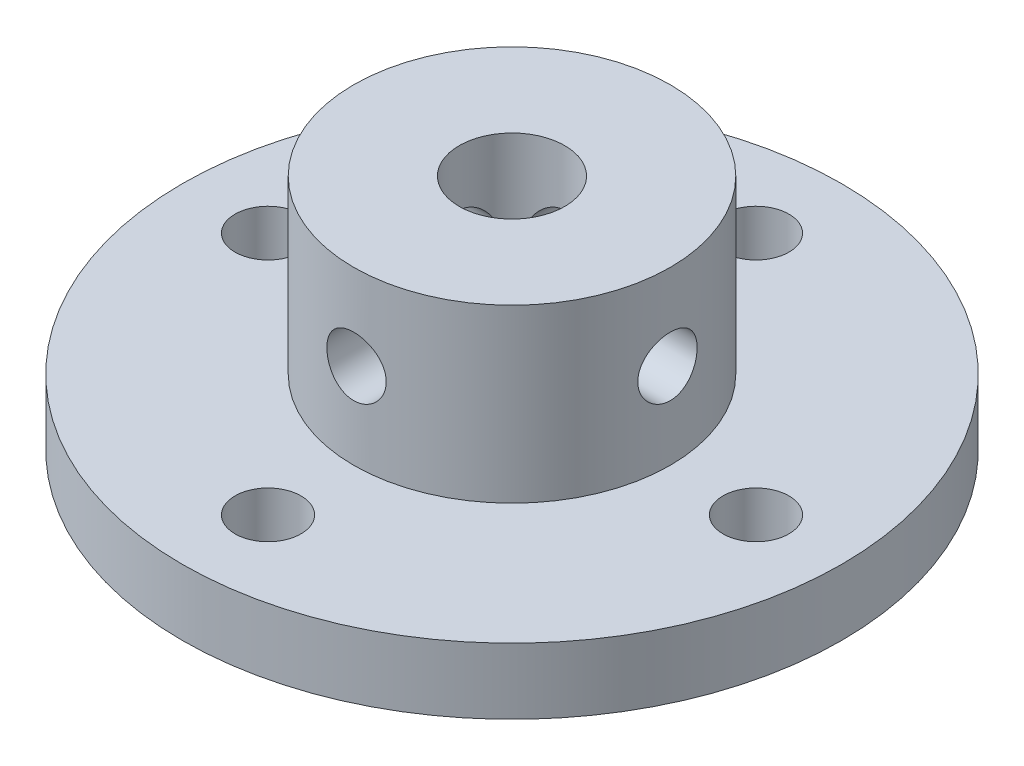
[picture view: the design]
ISO-10303-21;
HEADER;
FILE_DESCRIPTION(('STEP AP214'),'2;1');
FILE_NAME('part.step','',(''),(''),'','','');
FILE_SCHEMA(('AUTOMOTIVE_DESIGN { 1 0 10303 214 1 1 1 1 }'));
ENDSEC;
DATA;
#1=APPLICATION_CONTEXT('core data for automotive mechanical design processes');
#2=APPLICATION_PROTOCOL_DEFINITION('international standard','automotive_design',2000,#1);
#3=PRODUCT_CONTEXT('',#1,'mechanical');
#4=PRODUCT('Part','Part','',(#3));
#5=PRODUCT_RELATED_PRODUCT_CATEGORY('part','',(#4));
#6=PRODUCT_DEFINITION_FORMATION('','',#4);
#7=PRODUCT_DEFINITION_CONTEXT('part definition',#1,'design');
#8=PRODUCT_DEFINITION('design','',#6,#7);
#9=PRODUCT_DEFINITION_SHAPE('','',#8);
#10=(LENGTH_UNIT() NAMED_UNIT(*) SI_UNIT(.MILLI.,.METRE.));
#11=(NAMED_UNIT(*) PLANE_ANGLE_UNIT() SI_UNIT($,.RADIAN.));
#12=(NAMED_UNIT(*) SI_UNIT($,.STERADIAN.) SOLID_ANGLE_UNIT());
#13=UNCERTAINTY_MEASURE_WITH_UNIT(LENGTH_MEASURE(1.E-05),#10,'distance_accuracy_value','');
#14=(GEOMETRIC_REPRESENTATION_CONTEXT(3) GLOBAL_UNCERTAINTY_ASSIGNED_CONTEXT((#13)) GLOBAL_UNIT_ASSIGNED_CONTEXT((#10,
#11,#12)) REPRESENTATION_CONTEXT('',''));
#15=CARTESIAN_POINT('',(0.,0.,0.));
#16=DIRECTION('',(0.,0.,1.));
#17=DIRECTION('',(1.,0.,0.));
#18=AXIS2_PLACEMENT_3D('',#15,#16,#17);
#19=CARTESIAN_POINT('',(0.,5.,0.));
#20=DIRECTION('',(0.,-1.,0.));
#21=DIRECTION('',(0.,0.,-1.));
#22=AXIS2_PLACEMENT_3D('',#19,#20,#21);
#23=CYLINDRICAL_SURFACE('',#22,25.);
#24=CARTESIAN_POINT('',(0.,5.,0.));
#25=DIRECTION('',(0.,1.,0.));
#26=DIRECTION('',(0.,0.,1.));
#27=AXIS2_PLACEMENT_3D('',#24,#25,#26);
#28=CIRCLE('',#27,25.);
#29=CARTESIAN_POINT('',(0.,5.,25.));
#30=VERTEX_POINT('',#29);
#31=EDGE_CURVE('E52',#30,#30,#28,.T.);
#32=ORIENTED_EDGE('',*,*,#31,.F.);
#33=EDGE_LOOP('',(#32));
#34=FACE_BOUND('',#33,.T.);
#35=CARTESIAN_POINT('',(0.,0.,0.));
#36=DIRECTION('',(0.,1.,0.));
#37=DIRECTION('',(0.,0.,1.));
#38=AXIS2_PLACEMENT_3D('',#35,#36,#37);
#39=CIRCLE('',#38,25.);
#40=CARTESIAN_POINT('',(0.,0.,25.));
#41=VERTEX_POINT('',#40);
#42=EDGE_CURVE('E59',#41,#41,#39,.T.);
#43=ORIENTED_EDGE('',*,*,#42,.T.);
#44=EDGE_LOOP('',(#43));
#45=FACE_BOUND('',#44,.T.);
#46=ADVANCED_FACE('F41',(#34,#45),#23,.T.);
#47=CARTESIAN_POINT('',(0.,5.,0.));
#48=DIRECTION('',(0.,1.,0.));
#49=DIRECTION('',(0.,0.,1.));
#50=AXIS2_PLACEMENT_3D('',#47,#48,#49);
#51=PLANE('',#50);
#52=CARTESIAN_POINT('',(0.,5.,-18.5));
#53=DIRECTION('',(0.,1.,0.));
#54=DIRECTION('',(0.,0.,1.));
#55=AXIS2_PLACEMENT_3D('',#52,#53,#54);
#56=CIRCLE('',#55,2.5);
#57=CARTESIAN_POINT('',(0.,5.,-16.));
#58=VERTEX_POINT('',#57);
#59=EDGE_CURVE('E183',#58,#58,#56,.T.);
#60=ORIENTED_EDGE('',*,*,#59,.F.);
#61=EDGE_LOOP('',(#60));
#62=FACE_BOUND('',#61,.T.);
#63=CARTESIAN_POINT('',(18.5,5.,0.));
#64=DIRECTION('',(0.,1.,0.));
#65=DIRECTION('',(0.,0.,1.));
#66=AXIS2_PLACEMENT_3D('',#63,#64,#65);
#67=CIRCLE('',#66,2.5);
#68=CARTESIAN_POINT('',(18.5,5.,2.5));
#69=VERTEX_POINT('',#68);
#70=EDGE_CURVE('E178',#69,#69,#67,.T.);
#71=ORIENTED_EDGE('',*,*,#70,.F.);
#72=EDGE_LOOP('',(#71));
#73=FACE_BOUND('',#72,.T.);
#74=CARTESIAN_POINT('',(0.,5.,18.5));
#75=DIRECTION('',(0.,1.,0.));
#76=DIRECTION('',(0.,0.,1.));
#77=AXIS2_PLACEMENT_3D('',#74,#75,#76);
#78=CIRCLE('',#77,2.5);
#79=CARTESIAN_POINT('',(0.,5.,21.));
#80=VERTEX_POINT('',#79);
#81=EDGE_CURVE('E175',#80,#80,#78,.T.);
#82=ORIENTED_EDGE('',*,*,#81,.F.);
#83=EDGE_LOOP('',(#82));
#84=FACE_BOUND('',#83,.T.);
#85=CARTESIAN_POINT('',(-18.5,5.,0.));
#86=DIRECTION('',(0.,1.,0.));
#87=DIRECTION('',(0.,0.,1.));
#88=AXIS2_PLACEMENT_3D('',#85,#86,#87);
#89=CIRCLE('',#88,2.5);
#90=CARTESIAN_POINT('',(-18.5,5.,2.5));
#91=VERTEX_POINT('',#90);
#92=EDGE_CURVE('E168',#91,#91,#89,.T.);
#93=ORIENTED_EDGE('',*,*,#92,.F.);
#94=EDGE_LOOP('',(#93));
#95=FACE_BOUND('',#94,.T.);
#96=CARTESIAN_POINT('',(0.,5.,0.));
#97=DIRECTION('',(0.,1.,0.));
#98=DIRECTION('',(0.,0.,1.));
#99=AXIS2_PLACEMENT_3D('',#96,#97,#98);
#100=CIRCLE('',#99,12.);
#101=CARTESIAN_POINT('',(0.,5.,12.));
#102=VERTEX_POINT('',#101);
#103=EDGE_CURVE('E10',#102,#102,#100,.T.);
#104=ORIENTED_EDGE('',*,*,#103,.F.);
#105=EDGE_LOOP('',(#104));
#106=FACE_BOUND('',#105,.T.);
#107=ORIENTED_EDGE('',*,*,#31,.T.);
#108=EDGE_LOOP('',(#107));
#109=FACE_BOUND('',#108,.T.);
#110=ADVANCED_FACE('F119',(#62,#73,#84,#95,#106,#109),#51,.T.);
#111=CARTESIAN_POINT('',(0.,0.,0.));
#112=DIRECTION('',(0.,1.,0.));
#113=DIRECTION('',(0.,0.,1.));
#114=AXIS2_PLACEMENT_3D('',#111,#112,#113);
#115=PLANE('',#114);
#116=CARTESIAN_POINT('',(0.,0.,-18.5));
#117=DIRECTION('',(0.,1.,0.));
#118=DIRECTION('',(0.,0.,1.));
#119=AXIS2_PLACEMENT_3D('',#116,#117,#118);
#120=CIRCLE('',#119,2.5);
#121=CARTESIAN_POINT('',(0.,0.,-16.));
#122=VERTEX_POINT('',#121);
#123=EDGE_CURVE('E165',#122,#122,#120,.T.);
#124=ORIENTED_EDGE('',*,*,#123,.T.);
#125=EDGE_LOOP('',(#124));
#126=FACE_BOUND('',#125,.T.);
#127=CARTESIAN_POINT('',(18.5,0.,0.));
#128=DIRECTION('',(0.,1.,0.));
#129=DIRECTION('',(0.,0.,1.));
#130=AXIS2_PLACEMENT_3D('',#127,#128,#129);
#131=CIRCLE('',#130,2.5);
#132=CARTESIAN_POINT('',(18.5,0.,2.5));
#133=VERTEX_POINT('',#132);
#134=EDGE_CURVE('E181',#133,#133,#131,.T.);
#135=ORIENTED_EDGE('',*,*,#134,.T.);
#136=EDGE_LOOP('',(#135));
#137=FACE_BOUND('',#136,.T.);
#138=CARTESIAN_POINT('',(0.,0.,18.5));
#139=DIRECTION('',(0.,1.,0.));
#140=DIRECTION('',(0.,0.,1.));
#141=AXIS2_PLACEMENT_3D('',#138,#139,#140);
#142=CIRCLE('',#141,2.5);
#143=CARTESIAN_POINT('',(0.,0.,21.));
#144=VERTEX_POINT('',#143);
#145=EDGE_CURVE('E174',#144,#144,#142,.T.);
#146=ORIENTED_EDGE('',*,*,#145,.T.);
#147=EDGE_LOOP('',(#146));
#148=FACE_BOUND('',#147,.T.);
#149=CARTESIAN_POINT('',(-18.5,0.,0.));
#150=DIRECTION('',(0.,1.,0.));
#151=DIRECTION('',(0.,0.,1.));
#152=AXIS2_PLACEMENT_3D('',#149,#150,#151);
#153=CIRCLE('',#152,2.5);
#154=CARTESIAN_POINT('',(-18.5,0.,2.5));
#155=VERTEX_POINT('',#154);
#156=EDGE_CURVE('E169',#155,#155,#153,.T.);
#157=ORIENTED_EDGE('',*,*,#156,.T.);
#158=EDGE_LOOP('',(#157));
#159=FACE_BOUND('',#158,.T.);
#160=CARTESIAN_POINT('',(0.,0.,0.));
#161=DIRECTION('',(0.,1.,0.));
#162=DIRECTION('',(0.,0.,1.));
#163=AXIS2_PLACEMENT_3D('',#160,#161,#162);
#164=CIRCLE('',#163,4.);
#165=CARTESIAN_POINT('',(0.,0.,4.));
#166=VERTEX_POINT('',#165);
#167=EDGE_CURVE('E160',#166,#166,#164,.T.);
#168=ORIENTED_EDGE('',*,*,#167,.T.);
#169=EDGE_LOOP('',(#168));
#170=FACE_BOUND('',#169,.T.);
#171=ORIENTED_EDGE('',*,*,#42,.F.);
#172=EDGE_LOOP('',(#171));
#173=FACE_BOUND('',#172,.T.);
#174=ADVANCED_FACE('F117',(#126,#137,#148,#159,#170,#173),#115,.F.);
#175=CARTESIAN_POINT('',(0.,18.,0.));
#176=DIRECTION('',(0.,-1.,0.));
#177=DIRECTION('',(0.,0.,-1.));
#178=AXIS2_PLACEMENT_3D('',#175,#176,#177);
#179=CYLINDRICAL_SURFACE('',#178,12.);
#180=CARTESIAN_POINT('',(0.,13.75,-12.));
#181=CARTESIAN_POINT('',(-0.125207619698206,13.7499952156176,-11.9999977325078));
#182=CARTESIAN_POINT('',(-0.250477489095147,13.7395133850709,-11.9980201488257));
#183=CARTESIAN_POINT('',(-0.497487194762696,13.6978900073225,-11.9903217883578));
#184=CARTESIAN_POINT('',(-0.619223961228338,13.6667310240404,-11.9845978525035));
#185=CARTESIAN_POINT('',(-0.855559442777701,13.584740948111,-11.9700470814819));
#186=CARTESIAN_POINT('',(-0.970164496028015,13.5339276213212,-11.9612230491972));
#187=CARTESIAN_POINT('',(-1.18921195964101,13.4141216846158,-11.9414356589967));
#188=CARTESIAN_POINT('',(-1.29365519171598,13.3451305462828,-11.9304724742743));
#189=CARTESIAN_POINT('',(-1.49067557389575,13.1900503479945,-11.9074700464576));
#190=CARTESIAN_POINT('',(-1.58311343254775,13.1037858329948,-11.8954205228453));
#191=CARTESIAN_POINT('',(-1.75229409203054,12.9169850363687,-11.8716797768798));
#192=CARTESIAN_POINT('',(-1.82903576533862,12.8164477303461,-11.8599885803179));
#193=CARTESIAN_POINT('',(-1.96522497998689,12.602970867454,-11.8381882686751));
#194=CARTESIAN_POINT('',(-2.02453082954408,12.4899394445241,-11.8280924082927));
#195=CARTESIAN_POINT('',(-2.12325786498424,12.2552966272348,-11.8107706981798));
#196=CARTESIAN_POINT('',(-2.16268076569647,12.1336859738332,-11.8035446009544));
#197=CARTESIAN_POINT('',(-2.2200758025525,11.8868271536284,-11.7928840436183));
#198=CARTESIAN_POINT('',(-2.23829085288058,11.7616373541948,-11.7894066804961));
#199=CARTESIAN_POINT('',(-2.2535071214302,11.5099339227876,-11.7865079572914));
#200=CARTESIAN_POINT('',(-2.25051024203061,11.3834204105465,-11.7870862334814));
#201=CARTESIAN_POINT('',(-2.22358469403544,11.1344207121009,-11.7921943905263));
#202=CARTESIAN_POINT('',(-2.19993224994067,11.0119034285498,-11.79667212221));
#203=CARTESIAN_POINT('',(-2.1328019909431,10.7726073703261,-11.80899274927));
#204=CARTESIAN_POINT('',(-2.08932333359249,10.655828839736,-11.8168357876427));
#205=CARTESIAN_POINT('',(-1.9835047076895,10.4305169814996,-11.8350578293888));
#206=CARTESIAN_POINT('',(-1.92105320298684,10.3220372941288,-11.8454517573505));
#207=CARTESIAN_POINT('',(-1.77914053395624,10.1169929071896,-11.8675945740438));
#208=CARTESIAN_POINT('',(-1.69967764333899,10.0204294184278,-11.8793436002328));
#209=CARTESIAN_POINT('',(-1.52450858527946,9.84036256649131,-11.9031000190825));
#210=CARTESIAN_POINT('',(-1.42856615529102,9.75708902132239,-11.9151085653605));
#211=CARTESIAN_POINT('',(-1.22395205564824,9.60778413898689,-11.9378607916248));
#212=CARTESIAN_POINT('',(-1.11528025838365,9.54175297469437,-11.9486044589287));
#213=CARTESIAN_POINT('',(-0.888052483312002,9.42877336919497,-11.9676380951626));
#214=CARTESIAN_POINT('',(-0.76948434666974,9.38184883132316,-11.9759249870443));
#215=CARTESIAN_POINT('',(-0.525958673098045,9.30864686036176,-11.9890875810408));
#216=CARTESIAN_POINT('',(-0.401001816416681,9.28236723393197,-11.9939636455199));
#217=CARTESIAN_POINT('',(-0.150222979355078,9.25152095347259,-11.9997054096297));
#218=CARTESIAN_POINT('',(-0.0244410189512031,9.24663941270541,-12.0006292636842));
#219=CARTESIAN_POINT('',(0.226141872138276,9.25788321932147,-11.9985231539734));
#220=CARTESIAN_POINT('',(0.350942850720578,9.27400753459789,-11.9954933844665));
#221=CARTESIAN_POINT('',(0.595022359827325,9.32654355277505,-11.9858566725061));
#222=CARTESIAN_POINT('',(0.714336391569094,9.36279592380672,-11.9792778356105));
#223=CARTESIAN_POINT('',(0.945192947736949,9.45438656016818,-11.9632776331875));
#224=CARTESIAN_POINT('',(1.05673494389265,9.50972612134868,-11.95385607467));
#225=CARTESIAN_POINT('',(1.27022500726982,9.63861719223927,-11.933070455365));
#226=CARTESIAN_POINT('',(1.37205491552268,9.71236110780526,-11.9216862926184));
#227=CARTESIAN_POINT('',(1.56200748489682,9.87570720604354,-11.8982901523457));
#228=CARTESIAN_POINT('',(1.6501288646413,9.96531086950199,-11.8862781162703));
#229=CARTESIAN_POINT('',(1.81135943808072,10.1592584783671,-11.8627871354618));
#230=CARTESIAN_POINT('',(1.88425374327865,10.2637823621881,-11.8513173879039));
#231=CARTESIAN_POINT('',(2.0114501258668,10.4837764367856,-11.830394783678));
#232=CARTESIAN_POINT('',(2.06575289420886,10.5992462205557,-11.8209418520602));
#233=CARTESIAN_POINT('',(2.15392010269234,10.8373088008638,-11.8051953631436));
#234=CARTESIAN_POINT('',(2.18788303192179,10.959864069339,-11.7988866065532));
#235=CARTESIAN_POINT('',(2.23471018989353,11.2090708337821,-11.7901080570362));
#236=CARTESIAN_POINT('',(2.24757679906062,11.3357218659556,-11.7876378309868));
#237=CARTESIAN_POINT('',(2.25176643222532,11.5873724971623,-11.7868379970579));
#238=CARTESIAN_POINT('',(2.24342842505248,11.7123663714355,-11.7884432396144));
#239=CARTESIAN_POINT('',(2.20618763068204,11.9591371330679,-11.7954690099));
#240=CARTESIAN_POINT('',(2.17728496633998,12.0809140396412,-11.8008895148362));
#241=CARTESIAN_POINT('',(2.09987831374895,12.3176117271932,-11.8149076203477));
#242=CARTESIAN_POINT('',(2.05141103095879,12.4325448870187,-11.8234992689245));
#243=CARTESIAN_POINT('',(1.93628803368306,12.6527023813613,-11.8428958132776));
#244=CARTESIAN_POINT('',(1.86963103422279,12.7579260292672,-11.8537008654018));
#245=CARTESIAN_POINT('',(1.71884231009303,12.9573755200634,-11.8765089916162));
#246=CARTESIAN_POINT('',(1.63446389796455,13.0514131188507,-11.8885275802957));
#247=CARTESIAN_POINT('',(1.45114189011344,13.2241077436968,-11.912292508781));
#248=CARTESIAN_POINT('',(1.35219495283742,13.3027612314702,-11.9240387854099));
#249=CARTESIAN_POINT('',(1.14147741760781,13.4431164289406,-11.9460596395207));
#250=CARTESIAN_POINT('',(1.02959938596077,13.504659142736,-11.9563200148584));
#251=CARTESIAN_POINT('',(0.796935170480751,13.6079764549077,-11.9740742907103));
#252=CARTESIAN_POINT('',(0.676157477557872,13.6497696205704,-11.9815707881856));
#253=CARTESIAN_POINT('',(0.462520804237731,13.703915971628,-11.9914243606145));
#254=CARTESIAN_POINT('',(0.370910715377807,13.7211679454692,-11.9946220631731));
#255=CARTESIAN_POINT('',(0.186211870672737,13.7442115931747,-11.9989106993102));
#256=CARTESIAN_POINT('',(0.0931231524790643,13.7500035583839,-12.0000016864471));
#257=CARTESIAN_POINT('',(0.,13.75,-12.));
#258=B_SPLINE_CURVE_WITH_KNOTS('',3,(#180,#181,#182,#183,#184,#185,#186,#187,#188,#189,#190,
#191,#192,#193,#194,#195,#196,#197,#198,#199,#200,#201,#202,#203,#204,#205,#206,#207,#208,#209,
#210,#211,#212,#213,#214,#215,#216,#217,#218,#219,#220,#221,#222,#223,#224,#225,#226,#227,#228,
#229,#230,#231,#232,#233,#234,#235,#236,#237,#238,#239,#240,#241,#242,#243,#244,#245,#246,#247,
#248,#249,#250,#251,#252,#253,#254,#255,#256,#257),.UNSPECIFIED.,.T.,.F.,(4,2,2,2,2,2,2,2,2,2,2,
2,2,2,2,2,2,2,2,2,2,2,2,2,2,2,2,2,2,2,2,2,2,2,2,2,2,2,4),(0.,0.375282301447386,
0.750881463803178,1.12614190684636,1.50137198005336,1.88062677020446,2.25990879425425,
2.64219285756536,3.02444394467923,3.40227227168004,3.78006671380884,4.15288500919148,
4.5257191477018,4.90078893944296,5.27589681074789,5.65691652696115,6.03794006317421,
6.41943882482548,6.80089705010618,7.17672261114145,7.55252970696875,7.92540350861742,
8.29830263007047,8.67527667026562,9.05228592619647,9.43430155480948,9.81630298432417,
10.1964394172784,10.5765329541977,10.9505887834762,11.3246423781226,11.6979974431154,
12.0713788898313,12.4503505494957,12.8294092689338,13.2118807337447,13.5939919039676,
13.8731151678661,14.1522313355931),.UNSPECIFIED.);
#259=CARTESIAN_POINT('',(0.,13.75,-12.));
#260=VERTEX_POINT('',#259);
#261=EDGE_CURVE('E72',#260,#260,#258,.T.);
#262=ORIENTED_EDGE('',*,*,#261,.T.);
#263=EDGE_LOOP('',(#262));
#264=FACE_BOUND('',#263,.T.);
#265=CARTESIAN_POINT('',(2.25,11.5,11.7871752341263));
#266=CARTESIAN_POINT('',(2.24999519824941,11.3748141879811,11.787177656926));
#267=CARTESIAN_POINT('',(2.23951689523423,11.2495660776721,11.7891911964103));
#268=CARTESIAN_POINT('',(2.19790879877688,11.0026015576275,11.7970177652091));
#269=CARTESIAN_POINT('',(2.1667614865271,10.8808882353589,11.8028340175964));
#270=CARTESIAN_POINT('',(2.08480553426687,10.6446023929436,11.817584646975));
#271=CARTESIAN_POINT('',(2.03401520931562,10.530023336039,11.8265161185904));
#272=CARTESIAN_POINT('',(1.91426348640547,10.3110196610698,11.8464873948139));
#273=CARTESIAN_POINT('',(1.84530350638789,10.2065942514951,11.8575270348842));
#274=CARTESIAN_POINT('',(1.69025518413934,10.0095547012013,11.8806242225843));
#275=CARTESIAN_POINT('',(1.60398439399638,9.9170852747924,11.8926917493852));
#276=CARTESIAN_POINT('',(1.41715766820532,9.74784341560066,11.9163968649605));
#277=CARTESIAN_POINT('',(1.31660079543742,9.67107201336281,11.9280344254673));
#278=CARTESIAN_POINT('',(1.10310584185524,9.53485093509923,11.9496752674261));
#279=CARTESIAN_POINT('',(0.990079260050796,9.47553769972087,11.9596654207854));
#280=CARTESIAN_POINT('',(0.755446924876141,9.3767956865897,11.976774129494));
#281=CARTESIAN_POINT('',(0.633841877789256,9.33736527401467,11.983892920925));
#282=CARTESIAN_POINT('',(0.387004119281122,9.2799556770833,11.9943863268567));
#283=CARTESIAN_POINT('',(0.261829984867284,9.26173254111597,11.9978034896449));
#284=CARTESIAN_POINT('',(0.0101575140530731,9.2464946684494,12.0006552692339));
#285=CARTESIAN_POINT('',(-0.116340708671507,9.24947812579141,12.0000902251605));
#286=CARTESIAN_POINT('',(-0.365397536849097,9.27638165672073,11.9950745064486));
#287=CARTESIAN_POINT('',(-0.487985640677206,9.30003905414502,11.9906725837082));
#288=CARTESIAN_POINT('',(-0.727420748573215,9.36720347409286,11.9785323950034));
#289=CARTESIAN_POINT('',(-0.844267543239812,9.41071122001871,11.9707940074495));
#290=CARTESIAN_POINT('',(-1.06966509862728,9.51659159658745,11.9527689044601));
#291=CARTESIAN_POINT('',(-1.1781653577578,9.57906923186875,11.9424680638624));
#292=CARTESIAN_POINT('',(-1.38323996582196,9.72103850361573,11.9204572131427));
#293=CARTESIAN_POINT('',(-1.47981310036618,9.80053187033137,11.9087470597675));
#294=CARTESIAN_POINT('',(-1.65984842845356,9.9757235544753,11.8850027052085));
#295=CARTESIAN_POINT('',(-1.74308686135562,10.0716516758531,11.8729662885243));
#296=CARTESIAN_POINT('',(-1.89232757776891,10.2762242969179,11.8500976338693));
#297=CARTESIAN_POINT('',(-1.95832960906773,10.384868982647,11.8392654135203));
#298=CARTESIAN_POINT('',(-2.07128778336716,10.612087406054,11.8200283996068));
#299=CARTESIAN_POINT('',(-2.11821140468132,10.730677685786,11.8116277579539));
#300=CARTESIAN_POINT('',(-2.19140485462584,10.9742517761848,11.7982686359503));
#301=CARTESIAN_POINT('',(-2.21767702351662,11.0992348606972,11.7933097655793));
#302=CARTESIAN_POINT('',(-2.24849508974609,11.3500289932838,11.7874728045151));
#303=CARTESIAN_POINT('',(-2.25336246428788,11.4757991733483,11.786534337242));
#304=CARTESIAN_POINT('',(-2.24209453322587,11.7263551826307,11.7886828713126));
#305=CARTESIAN_POINT('',(-2.2259602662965,11.8511410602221,11.7917696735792));
#306=CARTESIAN_POINT('',(-2.17342302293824,12.0951293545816,11.8015647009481));
#307=CARTESIAN_POINT('',(-2.13718857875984,12.2143693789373,11.8082428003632));
#308=CARTESIAN_POINT('',(-2.0456583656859,12.4450857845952,11.8244420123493));
#309=CARTESIAN_POINT('',(-1.99036119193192,12.556561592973,11.8339633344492));
#310=CARTESIAN_POINT('',(-1.8615352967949,12.7700014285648,11.8549136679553));
#311=CARTESIAN_POINT('',(-1.78780349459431,12.8718408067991,11.8663634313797));
#312=CARTESIAN_POINT('',(-1.6244751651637,13.0618180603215,11.8898221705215));
#313=CARTESIAN_POINT('',(-1.53487721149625,13.1499547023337,11.9018311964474));
#314=CARTESIAN_POINT('',(-1.34092412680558,13.3112256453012,11.9252493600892));
#315=CARTESIAN_POINT('',(-1.23638780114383,13.384143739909,11.9366483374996));
#316=CARTESIAN_POINT('',(-1.01636178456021,13.5113818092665,11.9573910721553));
#317=CARTESIAN_POINT('',(-0.90087251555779,13.5657025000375,11.9667349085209));
#318=CARTESIAN_POINT('',(-0.662816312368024,13.6538801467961,11.9822708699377));
#319=CARTESIAN_POINT('',(-0.54028981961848,13.6878432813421,11.9884793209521));
#320=CARTESIAN_POINT('',(-0.291144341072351,13.7346805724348,11.9971146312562));
#321=CARTESIAN_POINT('',(-0.164525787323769,13.7475569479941,11.9995418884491));
#322=CARTESIAN_POINT('',(0.0871361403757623,13.7517779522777,12.0003334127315));
#323=CARTESIAN_POINT('',(0.212173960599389,13.7434491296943,11.998759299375));
#324=CARTESIAN_POINT('',(0.459035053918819,13.7062113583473,11.991852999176));
#325=CARTESIAN_POINT('',(0.580858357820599,13.6773026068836,11.9865208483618));
#326=CARTESIAN_POINT('',(0.817659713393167,13.5998631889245,11.9726975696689));
#327=CARTESIAN_POINT('',(0.932649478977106,13.5513672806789,11.9642120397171));
#328=CARTESIAN_POINT('',(1.15290844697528,13.4361693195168,11.9450005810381));
#329=CARTESIAN_POINT('',(1.25817699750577,13.3694660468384,11.9342745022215));
#330=CARTESIAN_POINT('',(1.45763254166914,13.2186228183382,11.9115716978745));
#331=CARTESIAN_POINT('',(1.5516393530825,13.1342469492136,11.8995792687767));
#332=CARTESIAN_POINT('',(1.72427304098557,12.9509431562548,11.8757945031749));
#333=CARTESIAN_POINT('',(1.802896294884,12.8520118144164,11.8640022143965));
#334=CARTESIAN_POINT('',(1.94321450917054,12.6413103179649,11.8418336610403));
#335=CARTESIAN_POINT('',(2.00474610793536,12.5294298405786,11.8314715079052));
#336=CARTESIAN_POINT('',(2.10804198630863,12.2967613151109,11.8135062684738));
#337=CARTESIAN_POINT('',(2.14982492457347,12.175981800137,11.8059005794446));
#338=CARTESIAN_POINT('',(2.20394589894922,11.9623715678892,11.7958952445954));
#339=CARTESIAN_POINT('',(2.22118658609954,11.8707914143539,11.7926446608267));
#340=CARTESIAN_POINT('',(2.24421526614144,11.6861522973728,11.7882837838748));
#341=CARTESIAN_POINT('',(2.25000357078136,11.5930933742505,11.7871734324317));
#342=CARTESIAN_POINT('',(2.25,11.5,11.7871752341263));
#343=B_SPLINE_CURVE_WITH_KNOTS('',3,(#265,#266,#267,#268,#269,#270,#271,#272,#273,#274,#275,
#276,#277,#278,#279,#280,#281,#282,#283,#284,#285,#286,#287,#288,#289,#290,#291,#292,#293,#294,
#295,#296,#297,#298,#299,#300,#301,#302,#303,#304,#305,#306,#307,#308,#309,#310,#311,#312,#313,
#314,#315,#316,#317,#318,#319,#320,#321,#322,#323,#324,#325,#326,#327,#328,#329,#330,#331,#332,
#333,#334,#335,#336,#337,#338,#339,#340,#341,#342),.UNSPECIFIED.,.T.,.F.,(4,2,2,2,2,2,2,2,2,2,2,
2,2,2,2,2,2,2,2,2,2,2,2,2,2,2,2,2,2,2,2,2,2,2,2,2,2,2,4),(0.,0.375216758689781,0.75075195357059,
1.12593784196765,1.50109445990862,1.88043503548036,2.25980050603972,2.64205656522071,
3.0242811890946,3.40206413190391,3.77981490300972,4.15283475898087,4.52586820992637,
4.90100537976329,5.27618071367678,5.65710922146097,6.038043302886,6.419624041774,
6.80116153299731,7.17694872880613,7.55271734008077,7.92538188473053,8.29807389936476,
8.67506793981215,9.05209589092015,9.43416188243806,9.81621316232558,10.1962540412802,
10.57625492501,10.9504395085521,11.3246205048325,11.6981403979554,12.0716853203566,
12.4505769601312,12.8295577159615,13.2120450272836,13.5941702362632,13.8732046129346,
14.1522313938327),.UNSPECIFIED.);
#344=CARTESIAN_POINT('',(2.25,11.5,11.7871752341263));
#345=VERTEX_POINT('',#344);
#346=EDGE_CURVE('E121',#345,#345,#343,.T.);
#347=ORIENTED_EDGE('',*,*,#346,.T.);
#348=EDGE_LOOP('',(#347));
#349=FACE_BOUND('',#348,.T.);
#350=CARTESIAN_POINT('',(-11.7871752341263,11.5,-2.25));
#351=CARTESIAN_POINT('',(-11.787177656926,11.6251858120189,-2.24999519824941));
#352=CARTESIAN_POINT('',(-11.7891911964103,11.7504339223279,-2.23951689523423));
#353=CARTESIAN_POINT('',(-11.7970177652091,11.9973984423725,-2.19790879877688));
#354=CARTESIAN_POINT('',(-11.8028340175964,12.1191117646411,-2.1667614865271));
#355=CARTESIAN_POINT('',(-11.817584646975,12.3553976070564,-2.08480553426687));
#356=CARTESIAN_POINT('',(-11.8265161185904,12.469976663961,-2.03401520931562));
#357=CARTESIAN_POINT('',(-11.8464873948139,12.6889803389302,-1.91426348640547));
#358=CARTESIAN_POINT('',(-11.8575270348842,12.7934057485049,-1.84530350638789));
#359=CARTESIAN_POINT('',(-11.8806242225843,12.9904452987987,-1.69025518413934));
#360=CARTESIAN_POINT('',(-11.8926917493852,13.0829147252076,-1.60398439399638));
#361=CARTESIAN_POINT('',(-11.9163968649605,13.2521565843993,-1.41715766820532));
#362=CARTESIAN_POINT('',(-11.9280344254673,13.3289279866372,-1.31660079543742));
#363=CARTESIAN_POINT('',(-11.9496752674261,13.4651490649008,-1.10310584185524));
#364=CARTESIAN_POINT('',(-11.9596654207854,13.5244623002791,-0.990079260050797));
#365=CARTESIAN_POINT('',(-11.976774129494,13.6232043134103,-0.755446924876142));
#366=CARTESIAN_POINT('',(-11.983892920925,13.6626347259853,-0.633841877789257));
#367=CARTESIAN_POINT('',(-11.9943863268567,13.7200443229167,-0.387004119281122));
#368=CARTESIAN_POINT('',(-11.9978034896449,13.738267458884,-0.261829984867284));
#369=CARTESIAN_POINT('',(-12.0006552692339,13.7535053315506,-0.0101575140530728));
#370=CARTESIAN_POINT('',(-12.0000902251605,13.7505218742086,0.116340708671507));
#371=CARTESIAN_POINT('',(-11.9950745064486,13.7236183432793,0.365397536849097));
#372=CARTESIAN_POINT('',(-11.9906725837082,13.699960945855,0.487985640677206));
#373=CARTESIAN_POINT('',(-11.9785323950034,13.6327965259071,0.727420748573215));
#374=CARTESIAN_POINT('',(-11.9707940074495,13.5892887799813,0.844267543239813));
#375=CARTESIAN_POINT('',(-11.9527689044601,13.4834084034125,1.06966509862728));
#376=CARTESIAN_POINT('',(-11.9424680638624,13.4209307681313,1.1781653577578));
#377=CARTESIAN_POINT('',(-11.9204572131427,13.2789614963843,1.38323996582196));
#378=CARTESIAN_POINT('',(-11.9087470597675,13.1994681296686,1.47981310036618));
#379=CARTESIAN_POINT('',(-11.8850027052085,13.0242764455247,1.65984842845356));
#380=CARTESIAN_POINT('',(-11.8729662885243,12.9283483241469,1.74308686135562));
#381=CARTESIAN_POINT('',(-11.8500976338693,12.7237757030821,1.89232757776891));
#382=CARTESIAN_POINT('',(-11.8392654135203,12.615131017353,1.95832960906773));
#383=CARTESIAN_POINT('',(-11.8200283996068,12.387912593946,2.07128778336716));
#384=CARTESIAN_POINT('',(-11.8116277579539,12.269322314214,2.11821140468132));
#385=CARTESIAN_POINT('',(-11.7982686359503,12.0257482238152,2.19140485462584));
#386=CARTESIAN_POINT('',(-11.7933097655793,11.9007651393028,2.21767702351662));
#387=CARTESIAN_POINT('',(-11.7874728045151,11.6499710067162,2.24849508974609));
#388=CARTESIAN_POINT('',(-11.786534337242,11.5242008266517,2.25336246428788));
#389=CARTESIAN_POINT('',(-11.7886828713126,11.2736448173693,2.24209453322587));
#390=CARTESIAN_POINT('',(-11.7917696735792,11.1488589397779,2.2259602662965));
#391=CARTESIAN_POINT('',(-11.8015647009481,10.9048706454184,2.17342302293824));
#392=CARTESIAN_POINT('',(-11.8082428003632,10.7856306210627,2.13718857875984));
#393=CARTESIAN_POINT('',(-11.8244420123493,10.5549142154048,2.0456583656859));
#394=CARTESIAN_POINT('',(-11.8339633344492,10.443438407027,1.99036119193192));
#395=CARTESIAN_POINT('',(-11.8549136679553,10.2299985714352,1.8615352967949));
#396=CARTESIAN_POINT('',(-11.8663634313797,10.1281591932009,1.78780349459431));
#397=CARTESIAN_POINT('',(-11.8898221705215,9.9381819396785,1.6244751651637));
#398=CARTESIAN_POINT('',(-11.9018311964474,9.85004529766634,1.53487721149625));
#399=CARTESIAN_POINT('',(-11.9252493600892,9.68877435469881,1.34092412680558));
#400=CARTESIAN_POINT('',(-11.9366483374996,9.61585626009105,1.23638780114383));
#401=CARTESIAN_POINT('',(-11.9573910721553,9.4886181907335,1.01636178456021));
#402=CARTESIAN_POINT('',(-11.9667349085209,9.43429749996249,0.900872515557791));
#403=CARTESIAN_POINT('',(-11.9822708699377,9.34611985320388,0.662816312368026));
#404=CARTESIAN_POINT('',(-11.9884793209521,9.31215671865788,0.540289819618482));
#405=CARTESIAN_POINT('',(-11.9971146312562,9.26531942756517,0.291144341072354));
#406=CARTESIAN_POINT('',(-11.9995418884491,9.25244305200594,0.16452578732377));
#407=CARTESIAN_POINT('',(-12.0003334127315,9.24822204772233,-0.0871361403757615));
#408=CARTESIAN_POINT('',(-11.998759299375,9.25655087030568,-0.212173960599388));
#409=CARTESIAN_POINT('',(-11.991852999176,9.29378864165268,-0.459035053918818));
#410=CARTESIAN_POINT('',(-11.9865208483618,9.32269739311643,-0.580858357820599));
#411=CARTESIAN_POINT('',(-11.9726975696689,9.40013681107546,-0.817659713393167));
#412=CARTESIAN_POINT('',(-11.9642120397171,9.44863271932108,-0.932649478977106));
#413=CARTESIAN_POINT('',(-11.9450005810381,9.56383068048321,-1.15290844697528));
#414=CARTESIAN_POINT('',(-11.9342745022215,9.6305339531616,-1.25817699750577));
#415=CARTESIAN_POINT('',(-11.9115716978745,9.78137718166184,-1.45763254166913));
#416=CARTESIAN_POINT('',(-11.8995792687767,9.86575305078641,-1.5516393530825));
#417=CARTESIAN_POINT('',(-11.8757945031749,10.0490568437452,-1.72427304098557));
#418=CARTESIAN_POINT('',(-11.8640022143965,10.1479881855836,-1.802896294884));
#419=CARTESIAN_POINT('',(-11.8418336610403,10.3586896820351,-1.94321450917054));
#420=CARTESIAN_POINT('',(-11.8314715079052,10.4705701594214,-2.00474610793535));
#421=CARTESIAN_POINT('',(-11.8135062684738,10.7032386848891,-2.10804198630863));
#422=CARTESIAN_POINT('',(-11.8059005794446,10.824018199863,-2.14982492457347));
#423=CARTESIAN_POINT('',(-11.7958952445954,11.0376284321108,-2.20394589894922));
#424=CARTESIAN_POINT('',(-11.7926446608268,11.1292085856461,-2.22118658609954));
#425=CARTESIAN_POINT('',(-11.7882837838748,11.3138477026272,-2.24421526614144));
#426=CARTESIAN_POINT('',(-11.7871734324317,11.4069066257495,-2.25000357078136));
#427=CARTESIAN_POINT('',(-11.7871752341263,11.5,-2.25));
#428=B_SPLINE_CURVE_WITH_KNOTS('',3,(#350,#351,#352,#353,#354,#355,#356,#357,#358,#359,#360,
#361,#362,#363,#364,#365,#366,#367,#368,#369,#370,#371,#372,#373,#374,#375,#376,#377,#378,#379,
#380,#381,#382,#383,#384,#385,#386,#387,#388,#389,#390,#391,#392,#393,#394,#395,#396,#397,#398,
#399,#400,#401,#402,#403,#404,#405,#406,#407,#408,#409,#410,#411,#412,#413,#414,#415,#416,#417,
#418,#419,#420,#421,#422,#423,#424,#425,#426,#427),.UNSPECIFIED.,.T.,.F.,(4,2,2,2,2,2,2,2,2,2,2,
2,2,2,2,2,2,2,2,2,2,2,2,2,2,2,2,2,2,2,2,2,2,2,2,2,2,2,4),(0.,0.375216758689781,0.75075195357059,
1.12593784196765,1.50109445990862,1.88043503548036,2.25980050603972,2.64205656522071,
3.0242811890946,3.40206413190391,3.77981490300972,4.15283475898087,4.52586820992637,
4.90100537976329,5.27618071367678,5.65710922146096,6.038043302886,6.419624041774,
6.80116153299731,7.17694872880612,7.55271734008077,7.92538188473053,8.29807389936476,
8.67506793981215,9.05209589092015,9.43416188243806,9.81621316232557,10.1962540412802,
10.57625492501,10.9504395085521,11.3246205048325,11.6981403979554,12.0716853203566,
12.4505769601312,12.8295577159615,13.2120450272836,13.5941702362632,13.8732046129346,
14.1522313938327),.UNSPECIFIED.);
#429=CARTESIAN_POINT('',(-11.7871752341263,11.5,-2.25));
#430=VERTEX_POINT('',#429);
#431=EDGE_CURVE('E104',#430,#430,#428,.T.);
#432=ORIENTED_EDGE('',*,*,#431,.T.);
#433=EDGE_LOOP('',(#432));
#434=FACE_BOUND('',#433,.T.);
#435=CARTESIAN_POINT('',(11.7871752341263,11.5,-2.25));
#436=CARTESIAN_POINT('',(11.787177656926,11.3748141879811,-2.24999519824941));
#437=CARTESIAN_POINT('',(11.7891911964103,11.2495660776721,-2.23951689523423));
#438=CARTESIAN_POINT('',(11.7970177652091,11.0026015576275,-2.19790879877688));
#439=CARTESIAN_POINT('',(11.8028340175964,10.8808882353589,-2.1667614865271));
#440=CARTESIAN_POINT('',(11.817584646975,10.6446023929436,-2.08480553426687));
#441=CARTESIAN_POINT('',(11.8265161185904,10.530023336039,-2.03401520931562));
#442=CARTESIAN_POINT('',(11.8464873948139,10.3110196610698,-1.91426348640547));
#443=CARTESIAN_POINT('',(11.8575270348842,10.2065942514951,-1.84530350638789));
#444=CARTESIAN_POINT('',(11.8806242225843,10.0095547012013,-1.69025518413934));
#445=CARTESIAN_POINT('',(11.8926917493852,9.9170852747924,-1.60398439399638));
#446=CARTESIAN_POINT('',(11.9163968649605,9.74784341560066,-1.41715766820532));
#447=CARTESIAN_POINT('',(11.9280344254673,9.67107201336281,-1.31660079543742));
#448=CARTESIAN_POINT('',(11.9496752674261,9.53485093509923,-1.10310584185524));
#449=CARTESIAN_POINT('',(11.9596654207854,9.47553769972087,-0.990079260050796));
#450=CARTESIAN_POINT('',(11.976774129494,9.3767956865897,-0.755446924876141));
#451=CARTESIAN_POINT('',(11.983892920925,9.33736527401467,-0.633841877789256));
#452=CARTESIAN_POINT('',(11.9943863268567,9.2799556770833,-0.387004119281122));
#453=CARTESIAN_POINT('',(11.9978034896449,9.26173254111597,-0.261829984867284));
#454=CARTESIAN_POINT('',(12.0006552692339,9.2464946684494,-0.0101575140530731));
#455=CARTESIAN_POINT('',(12.0000902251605,9.24947812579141,0.116340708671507));
#456=CARTESIAN_POINT('',(11.9950745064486,9.27638165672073,0.365397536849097));
#457=CARTESIAN_POINT('',(11.9906725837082,9.30003905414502,0.487985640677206));
#458=CARTESIAN_POINT('',(11.9785323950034,9.36720347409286,0.727420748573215));
#459=CARTESIAN_POINT('',(11.9707940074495,9.41071122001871,0.844267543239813));
#460=CARTESIAN_POINT('',(11.9527689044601,9.51659159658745,1.06966509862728));
#461=CARTESIAN_POINT('',(11.9424680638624,9.57906923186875,1.1781653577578));
#462=CARTESIAN_POINT('',(11.9204572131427,9.72103850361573,1.38323996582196));
#463=CARTESIAN_POINT('',(11.9087470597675,9.80053187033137,1.47981310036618));
#464=CARTESIAN_POINT('',(11.8850027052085,9.9757235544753,1.65984842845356));
#465=CARTESIAN_POINT('',(11.8729662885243,10.0716516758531,1.74308686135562));
#466=CARTESIAN_POINT('',(11.8500976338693,10.2762242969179,1.89232757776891));
#467=CARTESIAN_POINT('',(11.8392654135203,10.384868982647,1.95832960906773));
#468=CARTESIAN_POINT('',(11.8200283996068,10.612087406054,2.07128778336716));
#469=CARTESIAN_POINT('',(11.8116277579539,10.730677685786,2.11821140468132));
#470=CARTESIAN_POINT('',(11.7982686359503,10.9742517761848,2.19140485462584));
#471=CARTESIAN_POINT('',(11.7933097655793,11.0992348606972,2.21767702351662));
#472=CARTESIAN_POINT('',(11.7874728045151,11.3500289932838,2.24849508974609));
#473=CARTESIAN_POINT('',(11.786534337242,11.4757991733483,2.25336246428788));
#474=CARTESIAN_POINT('',(11.7886828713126,11.7263551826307,2.24209453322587));
#475=CARTESIAN_POINT('',(11.7917696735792,11.8511410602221,2.2259602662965));
#476=CARTESIAN_POINT('',(11.8015647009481,12.0951293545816,2.17342302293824));
#477=CARTESIAN_POINT('',(11.8082428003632,12.2143693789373,2.13718857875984));
#478=CARTESIAN_POINT('',(11.8244420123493,12.4450857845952,2.0456583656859));
#479=CARTESIAN_POINT('',(11.8339633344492,12.556561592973,1.99036119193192));
#480=CARTESIAN_POINT('',(11.8549136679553,12.7700014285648,1.8615352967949));
#481=CARTESIAN_POINT('',(11.8663634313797,12.8718408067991,1.78780349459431));
#482=CARTESIAN_POINT('',(11.8898221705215,13.0618180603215,1.6244751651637));
#483=CARTESIAN_POINT('',(11.9018311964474,13.1499547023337,1.53487721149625));
#484=CARTESIAN_POINT('',(11.9252493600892,13.3112256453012,1.34092412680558));
#485=CARTESIAN_POINT('',(11.9366483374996,13.384143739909,1.23638780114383));
#486=CARTESIAN_POINT('',(11.9573910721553,13.5113818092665,1.01636178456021));
#487=CARTESIAN_POINT('',(11.9667349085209,13.5657025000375,0.900872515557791));
#488=CARTESIAN_POINT('',(11.9822708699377,13.6538801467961,0.662816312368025));
#489=CARTESIAN_POINT('',(11.9884793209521,13.6878432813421,0.540289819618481));
#490=CARTESIAN_POINT('',(11.9971146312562,13.7346805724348,0.291144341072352));
#491=CARTESIAN_POINT('',(11.9995418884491,13.7475569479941,0.16452578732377));
#492=CARTESIAN_POINT('',(12.0003334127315,13.7517779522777,-0.0871361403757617));
#493=CARTESIAN_POINT('',(11.998759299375,13.7434491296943,-0.212173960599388));
#494=CARTESIAN_POINT('',(11.991852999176,13.7062113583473,-0.459035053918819));
#495=CARTESIAN_POINT('',(11.9865208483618,13.6773026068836,-0.580858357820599));
#496=CARTESIAN_POINT('',(11.9726975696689,13.5998631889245,-0.817659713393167));
#497=CARTESIAN_POINT('',(11.9642120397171,13.5513672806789,-0.932649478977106));
#498=CARTESIAN_POINT('',(11.9450005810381,13.4361693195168,-1.15290844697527));
#499=CARTESIAN_POINT('',(11.9342745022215,13.3694660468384,-1.25817699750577));
#500=CARTESIAN_POINT('',(11.9115716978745,13.2186228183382,-1.45763254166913));
#501=CARTESIAN_POINT('',(11.8995792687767,13.1342469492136,-1.5516393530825));
#502=CARTESIAN_POINT('',(11.8757945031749,12.9509431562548,-1.72427304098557));
#503=CARTESIAN_POINT('',(11.8640022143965,12.8520118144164,-1.80289629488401));
#504=CARTESIAN_POINT('',(11.8418336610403,12.6413103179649,-1.94321450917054));
#505=CARTESIAN_POINT('',(11.8314715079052,12.5294298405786,-2.00474610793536));
#506=CARTESIAN_POINT('',(11.8135062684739,12.2967613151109,-2.10804198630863));
#507=CARTESIAN_POINT('',(11.8059005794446,12.175981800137,-2.14982492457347));
#508=CARTESIAN_POINT('',(11.7958952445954,11.9623715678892,-2.20394589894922));
#509=CARTESIAN_POINT('',(11.7926446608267,11.8707914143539,-2.22118658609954));
#510=CARTESIAN_POINT('',(11.7882837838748,11.6861522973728,-2.24421526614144));
#511=CARTESIAN_POINT('',(11.7871734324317,11.5930933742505,-2.25000357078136));
#512=CARTESIAN_POINT('',(11.7871752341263,11.5,-2.25));
#513=B_SPLINE_CURVE_WITH_KNOTS('',3,(#435,#436,#437,#438,#439,#440,#441,#442,#443,#444,#445,
#446,#447,#448,#449,#450,#451,#452,#453,#454,#455,#456,#457,#458,#459,#460,#461,#462,#463,#464,
#465,#466,#467,#468,#469,#470,#471,#472,#473,#474,#475,#476,#477,#478,#479,#480,#481,#482,#483,
#484,#485,#486,#487,#488,#489,#490,#491,#492,#493,#494,#495,#496,#497,#498,#499,#500,#501,#502,
#503,#504,#505,#506,#507,#508,#509,#510,#511,#512),.UNSPECIFIED.,.T.,.F.,(4,2,2,2,2,2,2,2,2,2,2,
2,2,2,2,2,2,2,2,2,2,2,2,2,2,2,2,2,2,2,2,2,2,2,2,2,2,2,4),(0.,0.375216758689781,0.75075195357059,
1.12593784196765,1.50109445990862,1.88043503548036,2.25980050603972,2.64205656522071,
3.0242811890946,3.40206413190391,3.77981490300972,4.15283475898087,4.52586820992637,
4.90100537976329,5.27618071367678,5.65710922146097,6.038043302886,6.419624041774,
6.80116153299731,7.17694872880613,7.55271734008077,7.92538188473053,8.29807389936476,
8.67506793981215,9.05209589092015,9.43416188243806,9.81621316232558,10.1962540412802,
10.57625492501,10.9504395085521,11.3246205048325,11.6981403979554,12.0716853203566,
12.4505769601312,12.8295577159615,13.2120450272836,13.5941702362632,13.8732046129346,
14.1522313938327),.UNSPECIFIED.);
#514=CARTESIAN_POINT('',(11.7871752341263,11.5,-2.25));
#515=VERTEX_POINT('',#514);
#516=EDGE_CURVE('E97',#515,#515,#513,.T.);
#517=ORIENTED_EDGE('',*,*,#516,.T.);
#518=EDGE_LOOP('',(#517));
#519=FACE_BOUND('',#518,.T.);
#520=CARTESIAN_POINT('',(0.,18.,0.));
#521=DIRECTION('',(0.,1.,0.));
#522=DIRECTION('',(0.,0.,1.));
#523=AXIS2_PLACEMENT_3D('',#520,#521,#522);
#524=CIRCLE('',#523,12.);
#525=CARTESIAN_POINT('',(0.,18.,12.));
#526=VERTEX_POINT('',#525);
#527=EDGE_CURVE('E64',#526,#526,#524,.T.);
#528=ORIENTED_EDGE('',*,*,#527,.F.);
#529=EDGE_LOOP('',(#528));
#530=FACE_BOUND('',#529,.T.);
#531=ORIENTED_EDGE('',*,*,#103,.T.);
#532=EDGE_LOOP('',(#531));
#533=FACE_BOUND('',#532,.T.);
#534=ADVANCED_FACE('F113',(#264,#349,#434,#519,#530,#533),#179,.T.);
#535=CARTESIAN_POINT('',(0.,18.,0.));
#536=DIRECTION('',(0.,1.,0.));
#537=DIRECTION('',(0.,0.,1.));
#538=AXIS2_PLACEMENT_3D('',#535,#536,#537);
#539=PLANE('',#538);
#540=CARTESIAN_POINT('',(0.,18.,0.));
#541=DIRECTION('',(0.,1.,0.));
#542=DIRECTION('',(0.,0.,1.));
#543=AXIS2_PLACEMENT_3D('',#540,#541,#542);
#544=CIRCLE('',#543,4.);
#545=CARTESIAN_POINT('',(0.,18.,4.));
#546=VERTEX_POINT('',#545);
#547=EDGE_CURVE('E157',#546,#546,#544,.T.);
#548=ORIENTED_EDGE('',*,*,#547,.F.);
#549=EDGE_LOOP('',(#548));
#550=FACE_BOUND('',#549,.T.);
#551=ORIENTED_EDGE('',*,*,#527,.T.);
#552=EDGE_LOOP('',(#551));
#553=FACE_BOUND('',#552,.T.);
#554=ADVANCED_FACE('F120',(#550,#553),#539,.T.);
#555=CARTESIAN_POINT('',(0.,0.,0.));
#556=DIRECTION('',(0.,1.,0.));
#557=DIRECTION('',(0.,0.,1.));
#558=AXIS2_PLACEMENT_3D('',#555,#556,#557);
#559=CYLINDRICAL_SURFACE('',#558,4.);
#560=CARTESIAN_POINT('',(0.,9.25,4.));
#561=CARTESIAN_POINT('',(0.116574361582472,9.24999453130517,4.00000478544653));
#562=CARTESIAN_POINT('',(0.23311749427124,9.2590981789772,3.99486161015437));
#563=CARTESIAN_POINT('',(0.462569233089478,9.29500258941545,3.97483223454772));
#564=CARTESIAN_POINT('',(0.57547749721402,9.32180501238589,3.95994512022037));
#565=CARTESIAN_POINT('',(0.794135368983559,9.39168584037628,3.92194301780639));
#566=CARTESIAN_POINT('',(0.899909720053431,9.43470417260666,3.89885841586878));
#567=CARTESIAN_POINT('',(1.10253378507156,9.53538019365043,3.84647695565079));
#568=CARTESIAN_POINT('',(1.19938128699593,9.59304149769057,3.81717856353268));
#569=CARTESIAN_POINT('',(1.38906915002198,9.72592775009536,3.75249587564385));
#570=CARTESIAN_POINT('',(1.48114339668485,9.80210554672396,3.71682789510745));
#571=CARTESIAN_POINT('',(1.65194589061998,9.96776263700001,3.64413342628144));
#572=CARTESIAN_POINT('',(1.73066006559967,10.0572557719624,3.60710555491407));
#573=CARTESIAN_POINT('',(1.88082299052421,10.2580941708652,3.53132973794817));
#574=CARTESIAN_POINT('',(1.95065199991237,10.3707458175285,3.49280663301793));
#575=CARTESIAN_POINT('',(2.07007441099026,10.6084228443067,3.42338878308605));
#576=CARTESIAN_POINT('',(2.11969745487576,10.7334297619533,3.3924828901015));
#577=CARTESIAN_POINT('',(2.18797418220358,10.9647229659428,3.34873790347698));
#578=CARTESIAN_POINT('',(2.21099236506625,11.0692560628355,3.33344311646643));
#579=CARTESIAN_POINT('',(2.24191937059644,11.281454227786,3.31272698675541));
#580=CARTESIAN_POINT('',(2.24984363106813,11.3891159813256,3.307295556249));
#581=CARTESIAN_POINT('',(2.25015198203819,11.6045987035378,3.30708570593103));
#582=CARTESIAN_POINT('',(2.24251729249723,11.7124197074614,3.31232016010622));
#583=CARTESIAN_POINT('',(2.212114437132,11.9249625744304,3.33269723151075));
#584=CARTESIAN_POINT('',(2.18933618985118,12.029682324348,3.34784644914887));
#585=CARTESIAN_POINT('',(2.12979203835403,12.2333027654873,3.38603292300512));
#586=CARTESIAN_POINT('',(2.09304699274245,12.3322118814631,3.40905841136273));
#587=CARTESIAN_POINT('',(2.00683191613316,12.5227794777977,3.46051165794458));
#588=CARTESIAN_POINT('',(1.95735695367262,12.6144351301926,3.48894150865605));
#589=CARTESIAN_POINT('',(1.83818085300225,12.8030329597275,3.55335821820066));
#590=CARTESIAN_POINT('',(1.76653038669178,12.8985786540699,3.58983262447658));
#591=CARTESIAN_POINT('',(1.60910062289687,13.077175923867,3.66310576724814));
#592=CARTESIAN_POINT('',(1.52330978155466,13.1602171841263,3.69990474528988));
#593=CARTESIAN_POINT('',(1.32903508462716,13.3203414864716,3.77433344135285));
#594=CARTESIAN_POINT('',(1.21910653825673,13.3958430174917,3.81163274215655));
#595=CARTESIAN_POINT('',(0.985819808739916,13.5269493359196,3.8785102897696));
#596=CARTESIAN_POINT('',(0.862470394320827,13.5825670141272,3.90809353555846));
#597=CARTESIAN_POINT('',(0.61480293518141,13.6680512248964,3.95433282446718));
#598=CARTESIAN_POINT('',(0.491161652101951,13.6994522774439,3.97175099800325));
#599=CARTESIAN_POINT('',(0.239312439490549,13.7408638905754,3.99482968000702));
#600=CARTESIAN_POINT('',(0.111108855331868,13.7508942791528,4.0005010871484));
#601=CARTESIAN_POINT('',(-0.13004078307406,13.7490900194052,3.99948985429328));
#602=CARTESIAN_POINT('',(-0.243020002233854,13.7396722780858,3.99417274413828));
#603=CARTESIAN_POINT('',(-0.465494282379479,13.7042007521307,3.97439096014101));
#604=CARTESIAN_POINT('',(-0.574989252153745,13.6781465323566,3.95992604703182));
#605=CARTESIAN_POINT('',(-0.786967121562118,13.6108014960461,3.92328872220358));
#606=CARTESIAN_POINT('',(-0.889490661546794,13.5696099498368,3.90116658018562));
#607=CARTESIAN_POINT('',(-1.08626635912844,13.4734562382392,3.85101918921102));
#608=CARTESIAN_POINT('',(-1.18051639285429,13.4184905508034,3.82299243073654));
#609=CARTESIAN_POINT('',(-1.36857667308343,13.2899122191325,3.76002936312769));
#610=CARTESIAN_POINT('',(-1.46132919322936,13.2149574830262,3.72467800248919));
#611=CARTESIAN_POINT('',(-1.63365800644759,13.0517004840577,3.65238471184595));
#612=CARTESIAN_POINT('',(-1.71321931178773,12.9633832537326,3.61544103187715));
#613=CARTESIAN_POINT('',(-1.86542341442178,12.7648897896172,3.53951439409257));
#614=CARTESIAN_POINT('',(-1.93645169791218,12.6533905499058,3.50072726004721));
#615=CARTESIAN_POINT('',(-2.05851857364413,12.4178923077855,3.43037744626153));
#616=CARTESIAN_POINT('',(-2.10958480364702,12.293910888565,3.398804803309));
#617=CARTESIAN_POINT('',(-2.18084463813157,12.063667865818,3.35340305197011));
#618=CARTESIAN_POINT('',(-2.20527701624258,11.9591803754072,3.33723657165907));
#619=CARTESIAN_POINT('',(-2.23899995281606,11.7467957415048,3.31471067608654));
#620=CARTESIAN_POINT('',(-2.24830655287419,11.6389023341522,3.30834087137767));
#621=CARTESIAN_POINT('',(-2.25127274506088,11.4226295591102,3.30632360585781));
#622=CARTESIAN_POINT('',(-2.24490785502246,11.3142496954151,3.31069292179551));
#623=CARTESIAN_POINT('',(-2.21685577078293,11.1003740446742,3.32953789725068));
#624=CARTESIAN_POINT('',(-2.19515878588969,10.9948801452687,3.34402001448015));
#625=CARTESIAN_POINT('',(-2.13778330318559,10.7903715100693,3.38097911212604));
#626=CARTESIAN_POINT('',(-2.10223255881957,10.6913069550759,3.40338287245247));
#627=CARTESIAN_POINT('',(-2.01839895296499,10.500269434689,3.45375909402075));
#628=CARTESIAN_POINT('',(-1.97011126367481,10.408299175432,3.48173366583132));
#629=CARTESIAN_POINT('',(-1.85366513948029,10.2191533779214,3.54527276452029));
#630=CARTESIAN_POINT('',(-1.78359984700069,10.1233209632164,3.58134425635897));
#631=CARTESIAN_POINT('',(-1.6294191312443,9.9438814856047,3.65407566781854));
#632=CARTESIAN_POINT('',(-1.54529224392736,9.86028450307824,3.69073604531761));
#633=CARTESIAN_POINT('',(-1.354021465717,9.69818149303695,3.76540884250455));
#634=CARTESIAN_POINT('',(-1.24535169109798,9.62131329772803,3.80310734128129));
#635=CARTESIAN_POINT('',(-1.01438833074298,9.48721203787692,3.87110760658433));
#636=CARTESIAN_POINT('',(-0.892101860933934,9.42996878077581,3.90141321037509));
#637=CARTESIAN_POINT('',(-0.643615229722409,9.3401824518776,3.94980432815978));
#638=CARTESIAN_POINT('',(-0.517920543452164,9.30654270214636,3.9684273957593));
#639=CARTESIAN_POINT('',(-0.261467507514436,9.26146515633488,3.99351673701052));
#640=CARTESIAN_POINT('',(-0.130714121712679,9.25000613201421,3.99999463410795));
#641=CARTESIAN_POINT('',(0.,9.25,4.));
#642=B_SPLINE_CURVE_WITH_KNOTS('',3,(#560,#561,#562,#563,#564,#565,#566,#567,#568,#569,#570,
#571,#572,#573,#574,#575,#576,#577,#578,#579,#580,#581,#582,#583,#584,#585,#586,#587,#588,#589,
#590,#591,#592,#593,#594,#595,#596,#597,#598,#599,#600,#601,#602,#603,#604,#605,#606,#607,#608,
#609,#610,#611,#612,#613,#614,#615,#616,#617,#618,#619,#620,#621,#622,#623,#624,#625,#626,#627,
#628,#629,#630,#631,#632,#633,#634,#635,#636,#637,#638,#639,#640,#641),.UNSPECIFIED.,.T.,.F.,(4,
2,2,2,2,2,2,2,2,2,2,2,2,2,2,2,2,2,2,2,2,2,2,2,2,2,2,2,2,2,2,2,2,2,2,2,2,2,2,2,4),(0.,
0.349217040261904,0.698466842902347,1.04643534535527,1.39448984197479,1.76712658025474,
2.14015341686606,2.55217610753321,2.96359216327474,3.28655752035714,3.60919237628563,
3.93221689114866,4.25545666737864,4.57821558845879,4.90109973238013,5.27422406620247,
5.64765453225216,6.06093560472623,6.47394825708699,6.85794726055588,7.24158982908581,
7.58042476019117,7.91926855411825,8.2559287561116,8.59267513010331,8.9643182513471,
9.33638077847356,9.74768136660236,10.1584104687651,10.4825563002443,10.8063581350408,
11.1306661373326,11.4551814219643,11.7767724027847,12.0984854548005,12.4692322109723,
12.8402827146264,13.2531861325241,13.6658747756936,14.0578250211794,14.4493999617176),.UNSPECIFIED.);
#643=CARTESIAN_POINT('',(0.,9.25,4.));
#644=VERTEX_POINT('',#643);
#645=EDGE_CURVE('E42',#644,#644,#642,.T.);
#646=ORIENTED_EDGE('',*,*,#645,.T.);
#647=EDGE_LOOP('',(#646));
#648=FACE_BOUND('',#647,.T.);
#649=CARTESIAN_POINT('',(2.25,11.5,-3.30718913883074));
#650=CARTESIAN_POINT('',(2.24998998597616,11.385208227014,-3.30720283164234));
#651=CARTESIAN_POINT('',(2.24115272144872,11.270323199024,-3.31326199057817));
#652=CARTESIAN_POINT('',(2.20634454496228,11.0442804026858,-3.33653258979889));
#653=CARTESIAN_POINT('',(2.18034631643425,10.9331288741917,-3.35376180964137));
#654=CARTESIAN_POINT('',(2.1128237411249,10.7182825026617,-3.39669677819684));
#655=CARTESIAN_POINT('',(2.07140028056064,10.6145443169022,-3.42234732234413));
#656=CARTESIAN_POINT('',(1.97451321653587,10.4155358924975,-3.47914410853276));
#657=CARTESIAN_POINT('',(1.91904627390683,10.320267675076,-3.51029165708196));
#658=CARTESIAN_POINT('',(1.78877118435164,10.1297863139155,-3.57858292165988));
#659=CARTESIAN_POINT('',(1.71253525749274,10.0356516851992,-3.61601218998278));
#660=CARTESIAN_POINT('',(1.54582974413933,9.86063158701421,-3.69035883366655));
#661=CARTESIAN_POINT('',(1.45535126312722,9.77975446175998,-3.72727587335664));
#662=CARTESIAN_POINT('',(1.25270944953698,9.62628851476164,-3.8004390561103));
#663=CARTESIAN_POINT('',(1.13932192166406,9.5551242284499,-3.83631825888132));
#664=CARTESIAN_POINT('',(0.8997826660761,9.43338570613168,-3.89944625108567));
#665=CARTESIAN_POINT('',(0.77364121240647,9.38279505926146,-3.92670191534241));
#666=CARTESIAN_POINT('',(0.523681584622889,9.30825009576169,-3.96741508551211));
#667=CARTESIAN_POINT('',(0.400600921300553,9.28237518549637,-3.98185970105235));
#668=CARTESIAN_POINT('',(0.151075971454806,9.25156921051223,-3.9990959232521));
#669=CARTESIAN_POINT('',(0.0246344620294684,9.24662136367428,-4.0018968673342));
#670=CARTESIAN_POINT('',(-0.213146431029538,9.25730848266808,-3.99589303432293));
#671=CARTESIAN_POINT('',(-0.32462482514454,9.27075111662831,-3.98832428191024));
#672=CARTESIAN_POINT('',(-0.543435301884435,9.31376797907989,-3.96444074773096));
#673=CARTESIAN_POINT('',(-0.650767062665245,9.34334345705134,-3.94812528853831));
#674=CARTESIAN_POINT('',(-0.859682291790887,9.41772458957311,-3.90798978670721));
#675=CARTESIAN_POINT('',(-0.961199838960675,9.46267531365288,-3.88409842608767));
#676=CARTESIAN_POINT('',(-1.155432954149,9.56619567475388,-3.83081347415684));
#677=CARTESIAN_POINT('',(-1.24814581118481,9.62476948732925,-3.80141819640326));
#678=CARTESIAN_POINT('',(-1.43314551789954,9.76125437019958,-3.73587457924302));
#679=CARTESIAN_POINT('',(-1.52424389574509,9.84058984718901,-3.69933884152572));
#680=CARTESIAN_POINT('',(-1.69255803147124,10.0126363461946,-3.62542637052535));
#681=CARTESIAN_POINT('',(-1.76975841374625,10.1053619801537,-3.58804875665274));
#682=CARTESIAN_POINT('',(-1.91538550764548,10.3120334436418,-3.51263905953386));
#683=CARTESIAN_POINT('',(-1.98229476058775,10.4271563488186,-3.47487862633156));
#684=CARTESIAN_POINT('',(-2.09539020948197,10.669560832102,-3.40788863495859));
#685=CARTESIAN_POINT('',(-2.14160040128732,10.7968281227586,-3.37864921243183));
#686=CARTESIAN_POINT('',(-2.192034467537,10.9887065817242,-3.34594244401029));
#687=CARTESIAN_POINT('',(-2.20546205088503,11.0500976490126,-3.33707999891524));
#688=CARTESIAN_POINT('',(-2.22716773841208,11.1741490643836,-3.32263419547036));
#689=CARTESIAN_POINT('',(-2.23544892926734,11.2368086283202,-3.31704887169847));
#690=CARTESIAN_POINT('',(-2.24670015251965,11.3627670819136,-3.30943885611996));
#691=CARTESIAN_POINT('',(-2.24967465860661,11.426065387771,-3.30741116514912));
#692=CARTESIAN_POINT('',(-2.25027513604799,11.5526779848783,-3.30700126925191));
#693=CARTESIAN_POINT('',(-2.24790176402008,11.6159922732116,-3.30861861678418));
#694=CARTESIAN_POINT('',(-2.23437139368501,11.7853682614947,-3.31778831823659));
#695=CARTESIAN_POINT('',(-2.21829925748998,11.8909074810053,-3.32865531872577));
#696=CARTESIAN_POINT('',(-2.17183241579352,12.0973960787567,-3.35915029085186));
#697=CARTESIAN_POINT('',(-2.14143081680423,12.1983432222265,-3.37878247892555));
#698=CARTESIAN_POINT('',(-2.06604953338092,12.3976287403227,-3.42541559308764));
#699=CARTESIAN_POINT('',(-2.02053570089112,12.4957015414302,-3.45267969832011));
#700=CARTESIAN_POINT('',(-1.91666076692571,12.6834001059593,-3.51140559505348));
#701=CARTESIAN_POINT('',(-1.85829351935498,12.7730217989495,-3.54286939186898));
#702=CARTESIAN_POINT('',(-1.7190397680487,12.9569968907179,-3.61274572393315));
#703=CARTESIAN_POINT('',(-1.63601976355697,13.0496360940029,-3.65144050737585));
#704=CARTESIAN_POINT('',(-1.45540802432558,13.2203905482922,-3.72711451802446));
#705=CARTESIAN_POINT('',(-1.35780677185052,13.2984962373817,-3.7640926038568));
#706=CARTESIAN_POINT('',(-1.14360035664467,13.4422273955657,-3.83478893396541));
#707=CARTESIAN_POINT('',(-1.02622124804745,13.5068661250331,-3.86819366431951));
#708=CARTESIAN_POINT('',(-0.77985962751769,13.614792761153,-3.92526975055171));
#709=CARTESIAN_POINT('',(-0.65088975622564,13.6581036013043,-3.94895155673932));
#710=CARTESIAN_POINT('',(-0.399394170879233,13.7176365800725,-3.98181720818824));
#711=CARTESIAN_POINT('',(-0.277588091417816,13.7362029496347,-3.99225029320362));
#712=CARTESIAN_POINT('',(-0.0321628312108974,13.7531237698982,-4.00175085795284));
#713=CARTESIAN_POINT('',(0.0914552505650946,13.7514900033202,-4.00082496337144));
#714=CARTESIAN_POINT('',(0.324371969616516,13.7292712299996,-3.98836885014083));
#715=CARTESIAN_POINT('',(0.433908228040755,13.7105160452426,-3.97786263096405));
#716=CARTESIAN_POINT('',(0.647992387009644,13.6574916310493,-3.94864297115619));
#717=CARTESIAN_POINT('',(0.752539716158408,13.6232206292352,-3.92992859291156));
#718=CARTESIAN_POINT('',(0.957461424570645,13.5392195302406,-3.8851790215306));
#719=CARTESIAN_POINT('',(1.05760509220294,13.4890420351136,-3.85893435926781));
#720=CARTESIAN_POINT('',(1.24835010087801,13.3752264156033,-3.80152063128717));
#721=CARTESIAN_POINT('',(1.33894779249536,13.3115831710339,-3.77034969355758));
#722=CARTESIAN_POINT('',(1.51940733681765,13.1640425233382,-3.70159253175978));
#723=CARTESIAN_POINT('',(1.60791870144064,13.0786407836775,-3.66368342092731));
#724=CARTESIAN_POINT('',(1.77005940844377,12.894449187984,-3.58816213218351));
#725=CARTESIAN_POINT('',(1.84366940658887,12.7956422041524,-3.55055040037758));
#726=CARTESIAN_POINT('',(1.97937004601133,12.5780574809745,-3.47685328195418));
#727=CARTESIAN_POINT('',(2.04015665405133,12.4583319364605,-3.44110222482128));
#728=CARTESIAN_POINT('',(2.1149804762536,12.2706465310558,-3.39524856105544));
#729=CARTESIAN_POINT('',(2.13718482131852,12.2067879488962,-3.38126734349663));
#730=CARTESIAN_POINT('',(2.1758728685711,12.0767748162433,-3.35650182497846));
#731=CARTESIAN_POINT('',(2.19236009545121,12.0106217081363,-3.34571555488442));
#732=CARTESIAN_POINT('',(2.22042804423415,11.8710426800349,-3.32716265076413));
#733=CARTESIAN_POINT('',(2.23149039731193,11.7974676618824,-3.31971941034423));
#734=CARTESIAN_POINT('',(2.24627926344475,11.6492748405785,-3.30972844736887));
#735=CARTESIAN_POINT('',(2.25000651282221,11.5746571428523,-3.30718023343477));
#736=CARTESIAN_POINT('',(2.25,11.5,-3.30718913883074));
#737=B_SPLINE_CURVE_WITH_KNOTS('',3,(#649,#650,#651,#652,#653,#654,#655,#656,#657,#658,#659,
#660,#661,#662,#663,#664,#665,#666,#667,#668,#669,#670,#671,#672,#673,#674,#675,#676,#677,#678,
#679,#680,#681,#682,#683,#684,#685,#686,#687,#688,#689,#690,#691,#692,#693,#694,#695,#696,#697,
#698,#699,#700,#701,#702,#703,#704,#705,#706,#707,#708,#709,#710,#711,#712,#713,#714,#715,#716,
#717,#718,#719,#720,#721,#722,#723,#724,#725,#726,#727,#728,#729,#730,#731,#732,#733,#734,#735,
#736),.UNSPECIFIED.,.T.,.F.,(4,2,2,2,2,2,2,2,2,2,2,2,2,2,2,2,2,2,2,2,2,2,2,2,2,2,2,2,2,2,2,2,2,
2,2,2,2,2,2,2,2,2,2,4),(0.,0.344066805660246,0.68868261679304,1.03108301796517,1.37356490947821,
1.75238780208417,2.13144821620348,2.54501229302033,2.95824583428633,3.33584820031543,
3.71314769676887,4.04917469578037,4.38522772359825,4.72454320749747,5.06396283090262,
5.44103976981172,5.81853134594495,6.23167855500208,6.64434556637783,6.83448583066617,
7.0245119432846,7.21437778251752,7.40422031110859,7.72451713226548,8.0449681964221,
8.37822852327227,8.71164855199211,9.1008149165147,9.49023642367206,9.90224689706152,
10.3138133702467,10.6826803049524,11.0513320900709,11.3846804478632,11.7180668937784,
12.0618158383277,12.4056957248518,12.7901872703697,13.1751747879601,13.5894788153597,
13.7963097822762,14.0030130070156,14.2268062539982,14.4505770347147),.UNSPECIFIED.);
#738=CARTESIAN_POINT('',(2.25,11.5,-3.30718913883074));
#739=VERTEX_POINT('',#738);
#740=EDGE_CURVE('E133',#739,#739,#737,.T.);
#741=ORIENTED_EDGE('',*,*,#740,.T.);
#742=EDGE_LOOP('',(#741));
#743=FACE_BOUND('',#742,.T.);
#744=CARTESIAN_POINT('',(-3.30718913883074,11.5,-2.25));
#745=CARTESIAN_POINT('',(-3.30720283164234,11.385208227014,-2.24998998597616));
#746=CARTESIAN_POINT('',(-3.31326199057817,11.270323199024,-2.24115272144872));
#747=CARTESIAN_POINT('',(-3.33653258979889,11.0442804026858,-2.20634454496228));
#748=CARTESIAN_POINT('',(-3.35376180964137,10.9331288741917,-2.18034631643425));
#749=CARTESIAN_POINT('',(-3.39669677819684,10.7182825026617,-2.1128237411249));
#750=CARTESIAN_POINT('',(-3.42234732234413,10.6145443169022,-2.07140028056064));
#751=CARTESIAN_POINT('',(-3.47914410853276,10.4155358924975,-1.97451321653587));
#752=CARTESIAN_POINT('',(-3.51029165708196,10.320267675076,-1.91904627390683));
#753=CARTESIAN_POINT('',(-3.57858292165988,10.1297863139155,-1.78877118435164));
#754=CARTESIAN_POINT('',(-3.61601218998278,10.0356516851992,-1.71253525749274));
#755=CARTESIAN_POINT('',(-3.69035883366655,9.86063158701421,-1.54582974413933));
#756=CARTESIAN_POINT('',(-3.72727587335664,9.77975446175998,-1.45535126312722));
#757=CARTESIAN_POINT('',(-3.8004390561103,9.62628851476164,-1.25270944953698));
#758=CARTESIAN_POINT('',(-3.83631825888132,9.5551242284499,-1.13932192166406));
#759=CARTESIAN_POINT('',(-3.89944625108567,9.43338570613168,-0.8997826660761));
#760=CARTESIAN_POINT('',(-3.92670191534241,9.38279505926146,-0.77364121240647));
#761=CARTESIAN_POINT('',(-3.96741508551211,9.30825009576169,-0.523681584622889));
#762=CARTESIAN_POINT('',(-3.98185970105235,9.28237518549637,-0.400600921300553));
#763=CARTESIAN_POINT('',(-3.9990959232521,9.25156921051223,-0.151075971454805));
#764=CARTESIAN_POINT('',(-4.0018968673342,9.24662136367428,-0.0246344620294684));
#765=CARTESIAN_POINT('',(-3.99589303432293,9.25730848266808,0.213146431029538));
#766=CARTESIAN_POINT('',(-3.98832428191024,9.27075111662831,0.32462482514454));
#767=CARTESIAN_POINT('',(-3.96444074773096,9.31376797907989,0.543435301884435));
#768=CARTESIAN_POINT('',(-3.94812528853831,9.34334345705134,0.650767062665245));
#769=CARTESIAN_POINT('',(-3.90798978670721,9.41772458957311,0.859682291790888));
#770=CARTESIAN_POINT('',(-3.88409842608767,9.46267531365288,0.961199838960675));
#771=CARTESIAN_POINT('',(-3.83081347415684,9.56619567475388,1.155432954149));
#772=CARTESIAN_POINT('',(-3.80141819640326,9.62476948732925,1.24814581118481));
#773=CARTESIAN_POINT('',(-3.73587457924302,9.76125437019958,1.43314551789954));
#774=CARTESIAN_POINT('',(-3.69933884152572,9.84058984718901,1.52424389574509));
#775=CARTESIAN_POINT('',(-3.62542637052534,10.0126363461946,1.69255803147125));
#776=CARTESIAN_POINT('',(-3.58804875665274,10.1053619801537,1.76975841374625));
#777=CARTESIAN_POINT('',(-3.51263905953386,10.3120334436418,1.91538550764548));
#778=CARTESIAN_POINT('',(-3.47487862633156,10.4271563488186,1.98229476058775));
#779=CARTESIAN_POINT('',(-3.40788863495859,10.669560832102,2.09539020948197));
#780=CARTESIAN_POINT('',(-3.37864921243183,10.7968281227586,2.14160040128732));
#781=CARTESIAN_POINT('',(-3.34594244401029,10.9887065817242,2.192034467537));
#782=CARTESIAN_POINT('',(-3.33707999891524,11.0500976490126,2.20546205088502));
#783=CARTESIAN_POINT('',(-3.32263419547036,11.1741490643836,2.22716773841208));
#784=CARTESIAN_POINT('',(-3.31704887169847,11.2368086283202,2.23544892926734));
#785=CARTESIAN_POINT('',(-3.30943885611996,11.3627670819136,2.24670015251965));
#786=CARTESIAN_POINT('',(-3.30741116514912,11.426065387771,2.24967465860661));
#787=CARTESIAN_POINT('',(-3.30700126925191,11.5526779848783,2.25027513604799));
#788=CARTESIAN_POINT('',(-3.30861861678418,11.6159922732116,2.24790176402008));
#789=CARTESIAN_POINT('',(-3.31778831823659,11.7853682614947,2.23437139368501));
#790=CARTESIAN_POINT('',(-3.32865531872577,11.8909074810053,2.21829925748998));
#791=CARTESIAN_POINT('',(-3.35915029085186,12.0973960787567,2.17183241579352));
#792=CARTESIAN_POINT('',(-3.37878247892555,12.1983432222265,2.14143081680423));
#793=CARTESIAN_POINT('',(-3.42541559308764,12.3976287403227,2.06604953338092));
#794=CARTESIAN_POINT('',(-3.45267969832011,12.4957015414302,2.02053570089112));
#795=CARTESIAN_POINT('',(-3.51140559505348,12.6834001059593,1.91666076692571));
#796=CARTESIAN_POINT('',(-3.54286939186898,12.7730217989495,1.85829351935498));
#797=CARTESIAN_POINT('',(-3.61274572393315,12.9569968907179,1.7190397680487));
#798=CARTESIAN_POINT('',(-3.65144050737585,13.0496360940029,1.63601976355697));
#799=CARTESIAN_POINT('',(-3.72711451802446,13.2203905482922,1.45540802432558));
#800=CARTESIAN_POINT('',(-3.7640926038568,13.2984962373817,1.35780677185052));
#801=CARTESIAN_POINT('',(-3.83478893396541,13.4422273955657,1.14360035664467));
#802=CARTESIAN_POINT('',(-3.86819366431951,13.5068661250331,1.02622124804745));
#803=CARTESIAN_POINT('',(-3.92526975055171,13.614792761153,0.77985962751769));
#804=CARTESIAN_POINT('',(-3.94895155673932,13.6581036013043,0.650889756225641));
#805=CARTESIAN_POINT('',(-3.98181720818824,13.7176365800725,0.399394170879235));
#806=CARTESIAN_POINT('',(-3.99225029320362,13.7362029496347,0.277588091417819));
#807=CARTESIAN_POINT('',(-4.00175085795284,13.7531237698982,0.0321628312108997));
#808=CARTESIAN_POINT('',(-4.00082496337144,13.7514900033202,-0.0914552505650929));
#809=CARTESIAN_POINT('',(-3.98836885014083,13.7292712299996,-0.324371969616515));
#810=CARTESIAN_POINT('',(-3.97786263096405,13.7105160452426,-0.433908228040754));
#811=CARTESIAN_POINT('',(-3.94864297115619,13.6574916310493,-0.647992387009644));
#812=CARTESIAN_POINT('',(-3.92992859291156,13.6232206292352,-0.752539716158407));
#813=CARTESIAN_POINT('',(-3.8851790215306,13.5392195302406,-0.957461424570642));
#814=CARTESIAN_POINT('',(-3.85893435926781,13.4890420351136,-1.05760509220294));
#815=CARTESIAN_POINT('',(-3.80152063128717,13.3752264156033,-1.24835010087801));
#816=CARTESIAN_POINT('',(-3.77034969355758,13.3115831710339,-1.33894779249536));
#817=CARTESIAN_POINT('',(-3.70159253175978,13.1640425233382,-1.51940733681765));
#818=CARTESIAN_POINT('',(-3.66368342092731,13.0786407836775,-1.60791870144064));
#819=CARTESIAN_POINT('',(-3.58816213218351,12.894449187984,-1.77005940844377));
#820=CARTESIAN_POINT('',(-3.55055040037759,12.7956422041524,-1.84366940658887));
#821=CARTESIAN_POINT('',(-3.47685328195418,12.5780574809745,-1.97937004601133));
#822=CARTESIAN_POINT('',(-3.44110222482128,12.4583319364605,-2.04015665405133));
#823=CARTESIAN_POINT('',(-3.39524856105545,12.2706465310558,-2.1149804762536));
#824=CARTESIAN_POINT('',(-3.38126734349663,12.2067879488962,-2.13718482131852));
#825=CARTESIAN_POINT('',(-3.35650182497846,12.0767748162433,-2.1758728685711));
#826=CARTESIAN_POINT('',(-3.34571555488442,12.0106217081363,-2.19236009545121));
#827=CARTESIAN_POINT('',(-3.32716265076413,11.8710426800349,-2.22042804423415));
#828=CARTESIAN_POINT('',(-3.31971941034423,11.7974676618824,-2.23149039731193));
#829=CARTESIAN_POINT('',(-3.30972844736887,11.6492748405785,-2.24627926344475));
#830=CARTESIAN_POINT('',(-3.30718023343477,11.5746571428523,-2.25000651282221));
#831=CARTESIAN_POINT('',(-3.30718913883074,11.5,-2.25));
#832=B_SPLINE_CURVE_WITH_KNOTS('',3,(#744,#745,#746,#747,#748,#749,#750,#751,#752,#753,#754,
#755,#756,#757,#758,#759,#760,#761,#762,#763,#764,#765,#766,#767,#768,#769,#770,#771,#772,#773,
#774,#775,#776,#777,#778,#779,#780,#781,#782,#783,#784,#785,#786,#787,#788,#789,#790,#791,#792,
#793,#794,#795,#796,#797,#798,#799,#800,#801,#802,#803,#804,#805,#806,#807,#808,#809,#810,#811,
#812,#813,#814,#815,#816,#817,#818,#819,#820,#821,#822,#823,#824,#825,#826,#827,#828,#829,#830,
#831),.UNSPECIFIED.,.T.,.F.,(4,2,2,2,2,2,2,2,2,2,2,2,2,2,2,2,2,2,2,2,2,2,2,2,2,2,2,2,2,2,2,2,2,
2,2,2,2,2,2,2,2,2,2,4),(0.,0.344066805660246,0.68868261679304,1.03108301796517,1.37356490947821,
1.75238780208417,2.13144821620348,2.54501229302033,2.95824583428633,3.33584820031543,
3.71314769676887,4.04917469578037,4.38522772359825,4.72454320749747,5.06396283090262,
5.44103976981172,5.81853134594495,6.23167855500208,6.64434556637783,6.83448583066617,
7.02451194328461,7.21437778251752,7.40422031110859,7.72451713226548,8.0449681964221,
8.37822852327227,8.71164855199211,9.1008149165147,9.49023642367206,9.90224689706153,
10.3138133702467,10.6826803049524,11.0513320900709,11.3846804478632,11.7180668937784,
12.0618158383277,12.4056957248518,12.7901872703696,13.1751747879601,13.5894788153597,
13.7963097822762,14.0030130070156,14.2268062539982,14.4505770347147),.UNSPECIFIED.);
#833=CARTESIAN_POINT('',(-3.30718913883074,11.5,-2.25));
#834=VERTEX_POINT('',#833);
#835=EDGE_CURVE('E71',#834,#834,#832,.T.);
#836=ORIENTED_EDGE('',*,*,#835,.T.);
#837=EDGE_LOOP('',(#836));
#838=FACE_BOUND('',#837,.T.);
#839=CARTESIAN_POINT('',(3.30718913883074,11.5,-2.25));
#840=CARTESIAN_POINT('',(3.30720283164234,11.614791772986,-2.24998998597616));
#841=CARTESIAN_POINT('',(3.31326199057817,11.729676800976,-2.24115272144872));
#842=CARTESIAN_POINT('',(3.33653258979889,11.9557195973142,-2.20634454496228));
#843=CARTESIAN_POINT('',(3.35376180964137,12.0668711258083,-2.18034631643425));
#844=CARTESIAN_POINT('',(3.39669677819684,12.2817174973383,-2.1128237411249));
#845=CARTESIAN_POINT('',(3.42234732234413,12.3854556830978,-2.07140028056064));
#846=CARTESIAN_POINT('',(3.47914410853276,12.5844641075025,-1.97451321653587));
#847=CARTESIAN_POINT('',(3.51029165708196,12.679732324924,-1.91904627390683));
#848=CARTESIAN_POINT('',(3.57858292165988,12.8702136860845,-1.78877118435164));
#849=CARTESIAN_POINT('',(3.61601218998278,12.9643483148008,-1.71253525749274));
#850=CARTESIAN_POINT('',(3.69035883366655,13.1393684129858,-1.54582974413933));
#851=CARTESIAN_POINT('',(3.72727587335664,13.22024553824,-1.45535126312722));
#852=CARTESIAN_POINT('',(3.8004390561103,13.3737114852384,-1.25270944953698));
#853=CARTESIAN_POINT('',(3.83631825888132,13.4448757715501,-1.13932192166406));
#854=CARTESIAN_POINT('',(3.89944625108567,13.5666142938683,-0.8997826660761));
#855=CARTESIAN_POINT('',(3.92670191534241,13.6172049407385,-0.77364121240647));
#856=CARTESIAN_POINT('',(3.96741508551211,13.6917499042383,-0.523681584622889));
#857=CARTESIAN_POINT('',(3.98185970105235,13.7176248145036,-0.400600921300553));
#858=CARTESIAN_POINT('',(3.9990959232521,13.7484307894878,-0.151075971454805));
#859=CARTESIAN_POINT('',(4.0018968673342,13.7533786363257,-0.0246344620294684));
#860=CARTESIAN_POINT('',(3.99589303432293,13.7426915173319,0.213146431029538));
#861=CARTESIAN_POINT('',(3.98832428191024,13.7292488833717,0.32462482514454));
#862=CARTESIAN_POINT('',(3.96444074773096,13.6862320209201,0.543435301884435));
#863=CARTESIAN_POINT('',(3.94812528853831,13.6566565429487,0.650767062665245));
#864=CARTESIAN_POINT('',(3.90798978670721,13.5822754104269,0.859682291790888));
#865=CARTESIAN_POINT('',(3.88409842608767,13.5373246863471,0.961199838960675));
#866=CARTESIAN_POINT('',(3.83081347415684,13.4338043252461,1.155432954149));
#867=CARTESIAN_POINT('',(3.80141819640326,13.3752305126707,1.24814581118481));
#868=CARTESIAN_POINT('',(3.73587457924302,13.2387456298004,1.43314551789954));
#869=CARTESIAN_POINT('',(3.69933884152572,13.159410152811,1.52424389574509));
#870=CARTESIAN_POINT('',(3.62542637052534,12.9873636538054,1.69255803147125));
#871=CARTESIAN_POINT('',(3.58804875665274,12.8946380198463,1.76975841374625));
#872=CARTESIAN_POINT('',(3.51263905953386,12.6879665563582,1.91538550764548));
#873=CARTESIAN_POINT('',(3.47487862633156,12.5728436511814,1.98229476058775));
#874=CARTESIAN_POINT('',(3.40788863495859,12.330439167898,2.09539020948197));
#875=CARTESIAN_POINT('',(3.37864921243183,12.2031718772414,2.14160040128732));
#876=CARTESIAN_POINT('',(3.34594244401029,12.0112934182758,2.192034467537));
#877=CARTESIAN_POINT('',(3.33707999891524,11.9499023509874,2.20546205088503));
#878=CARTESIAN_POINT('',(3.32263419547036,11.8258509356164,2.22716773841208));
#879=CARTESIAN_POINT('',(3.31704887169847,11.7631913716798,2.23544892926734));
#880=CARTESIAN_POINT('',(3.30943885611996,11.6372329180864,2.24670015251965));
#881=CARTESIAN_POINT('',(3.30741116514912,11.573934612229,2.24967465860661));
#882=CARTESIAN_POINT('',(3.30700126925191,11.4473220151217,2.25027513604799));
#883=CARTESIAN_POINT('',(3.30861861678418,11.3840077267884,2.24790176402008));
#884=CARTESIAN_POINT('',(3.31778831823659,11.2146317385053,2.23437139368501));
#885=CARTESIAN_POINT('',(3.32865531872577,11.1090925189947,2.21829925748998));
#886=CARTESIAN_POINT('',(3.35915029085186,10.9026039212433,2.17183241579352));
#887=CARTESIAN_POINT('',(3.37878247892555,10.8016567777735,2.14143081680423));
#888=CARTESIAN_POINT('',(3.42541559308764,10.6023712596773,2.06604953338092));
#889=CARTESIAN_POINT('',(3.45267969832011,10.5042984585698,2.02053570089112));
#890=CARTESIAN_POINT('',(3.51140559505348,10.3165998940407,1.91666076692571));
#891=CARTESIAN_POINT('',(3.54286939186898,10.2269782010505,1.85829351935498));
#892=CARTESIAN_POINT('',(3.61274572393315,10.0430031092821,1.7190397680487));
#893=CARTESIAN_POINT('',(3.65144050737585,9.9503639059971,1.63601976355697));
#894=CARTESIAN_POINT('',(3.72711451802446,9.77960945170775,1.45540802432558));
#895=CARTESIAN_POINT('',(3.7640926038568,9.70150376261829,1.35780677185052));
#896=CARTESIAN_POINT('',(3.83478893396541,9.55777260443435,1.14360035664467));
#897=CARTESIAN_POINT('',(3.86819366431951,9.49313387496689,1.02622124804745));
#898=CARTESIAN_POINT('',(3.92526975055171,9.38520723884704,0.77985962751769));
#899=CARTESIAN_POINT('',(3.94895155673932,9.34189639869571,0.650889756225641));
#900=CARTESIAN_POINT('',(3.98181720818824,9.28236341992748,0.399394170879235));
#901=CARTESIAN_POINT('',(3.99225029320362,9.26379705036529,0.277588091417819));
#902=CARTESIAN_POINT('',(4.00175085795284,9.24687623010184,0.0321628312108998));
#903=CARTESIAN_POINT('',(4.00082496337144,9.24850999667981,-0.0914552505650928));
#904=CARTESIAN_POINT('',(3.98836885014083,9.27072877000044,-0.324371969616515));
#905=CARTESIAN_POINT('',(3.97786263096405,9.28948395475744,-0.433908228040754));
#906=CARTESIAN_POINT('',(3.94864297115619,9.34250836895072,-0.647992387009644));
#907=CARTESIAN_POINT('',(3.92992859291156,9.37677937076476,-0.752539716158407));
#908=CARTESIAN_POINT('',(3.8851790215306,9.46078046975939,-0.957461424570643));
#909=CARTESIAN_POINT('',(3.85893435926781,9.51095796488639,-1.05760509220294));
#910=CARTESIAN_POINT('',(3.80152063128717,9.62477358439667,-1.24835010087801));
#911=CARTESIAN_POINT('',(3.77034969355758,9.68841682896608,-1.33894779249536));
#912=CARTESIAN_POINT('',(3.70159253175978,9.83595747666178,-1.51940733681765));
#913=CARTESIAN_POINT('',(3.66368342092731,9.92135921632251,-1.60791870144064));
#914=CARTESIAN_POINT('',(3.58816213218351,10.105550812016,-1.77005940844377));
#915=CARTESIAN_POINT('',(3.55055040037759,10.2043577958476,-1.84366940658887));
#916=CARTESIAN_POINT('',(3.47685328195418,10.4219425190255,-1.97937004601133));
#917=CARTESIAN_POINT('',(3.44110222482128,10.5416680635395,-2.04015665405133));
#918=CARTESIAN_POINT('',(3.39524856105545,10.7293534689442,-2.1149804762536));
#919=CARTESIAN_POINT('',(3.38126734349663,10.7932120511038,-2.13718482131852));
#920=CARTESIAN_POINT('',(3.35650182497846,10.9232251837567,-2.1758728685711));
#921=CARTESIAN_POINT('',(3.34571555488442,10.9893782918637,-2.19236009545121));
#922=CARTESIAN_POINT('',(3.32716265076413,11.1289573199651,-2.22042804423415));
#923=CARTESIAN_POINT('',(3.31971941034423,11.2025323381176,-2.23149039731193));
#924=CARTESIAN_POINT('',(3.30972844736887,11.3507251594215,-2.24627926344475));
#925=CARTESIAN_POINT('',(3.30718023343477,11.4253428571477,-2.25000651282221));
#926=CARTESIAN_POINT('',(3.30718913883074,11.5,-2.25));
#927=B_SPLINE_CURVE_WITH_KNOTS('',3,(#839,#840,#841,#842,#843,#844,#845,#846,#847,#848,#849,
#850,#851,#852,#853,#854,#855,#856,#857,#858,#859,#860,#861,#862,#863,#864,#865,#866,#867,#868,
#869,#870,#871,#872,#873,#874,#875,#876,#877,#878,#879,#880,#881,#882,#883,#884,#885,#886,#887,
#888,#889,#890,#891,#892,#893,#894,#895,#896,#897,#898,#899,#900,#901,#902,#903,#904,#905,#906,
#907,#908,#909,#910,#911,#912,#913,#914,#915,#916,#917,#918,#919,#920,#921,#922,#923,#924,#925,
#926),.UNSPECIFIED.,.T.,.F.,(4,2,2,2,2,2,2,2,2,2,2,2,2,2,2,2,2,2,2,2,2,2,2,2,2,2,2,2,2,2,2,2,2,
2,2,2,2,2,2,2,2,2,2,4),(0.,0.344066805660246,0.68868261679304,1.03108301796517,1.37356490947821,
1.75238780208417,2.13144821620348,2.54501229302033,2.95824583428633,3.33584820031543,
3.71314769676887,4.04917469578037,4.38522772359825,4.72454320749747,5.06396283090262,
5.44103976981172,5.81853134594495,6.23167855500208,6.64434556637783,6.83448583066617,
7.02451194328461,7.21437778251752,7.40422031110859,7.72451713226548,8.0449681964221,
8.37822852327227,8.71164855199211,9.1008149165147,9.49023642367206,9.90224689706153,
10.3138133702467,10.6826803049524,11.0513320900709,11.3846804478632,11.7180668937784,
12.0618158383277,12.4056957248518,12.7901872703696,13.1751747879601,13.5894788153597,
13.7963097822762,14.0030130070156,14.2268062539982,14.4505770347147),.UNSPECIFIED.);
#928=CARTESIAN_POINT('',(3.30718913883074,11.5,-2.25));
#929=VERTEX_POINT('',#928);
#930=EDGE_CURVE('E66',#929,#929,#927,.T.);
#931=ORIENTED_EDGE('',*,*,#930,.T.);
#932=EDGE_LOOP('',(#931));
#933=FACE_BOUND('',#932,.T.);
#934=ORIENTED_EDGE('',*,*,#167,.F.);
#935=EDGE_LOOP('',(#934));
#936=FACE_BOUND('',#935,.T.);
#937=ORIENTED_EDGE('',*,*,#547,.T.);
#938=EDGE_LOOP('',(#937));
#939=FACE_BOUND('',#938,.T.);
#940=ADVANCED_FACE('F76',(#648,#743,#838,#933,#936,#939),#559,.F.);
#941=CARTESIAN_POINT('',(-18.5,0.,0.));
#942=DIRECTION('',(0.,1.,0.));
#943=DIRECTION('',(0.,0.,1.));
#944=AXIS2_PLACEMENT_3D('',#941,#942,#943);
#945=CYLINDRICAL_SURFACE('',#944,2.5);
#946=ORIENTED_EDGE('',*,*,#156,.F.);
#947=EDGE_LOOP('',(#946));
#948=FACE_BOUND('',#947,.T.);
#949=ORIENTED_EDGE('',*,*,#92,.T.);
#950=EDGE_LOOP('',(#949));
#951=FACE_BOUND('',#950,.T.);
#952=ADVANCED_FACE('F225',(#948,#951),#945,.F.);
#953=CARTESIAN_POINT('',(0.,0.,18.5));
#954=DIRECTION('',(0.,1.,0.));
#955=DIRECTION('',(0.,0.,1.));
#956=AXIS2_PLACEMENT_3D('',#953,#954,#955);
#957=CYLINDRICAL_SURFACE('',#956,2.5);
#958=ORIENTED_EDGE('',*,*,#145,.F.);
#959=EDGE_LOOP('',(#958));
#960=FACE_BOUND('',#959,.T.);
#961=ORIENTED_EDGE('',*,*,#81,.T.);
#962=EDGE_LOOP('',(#961));
#963=FACE_BOUND('',#962,.T.);
#964=ADVANCED_FACE('F228',(#960,#963),#957,.F.);
#965=CARTESIAN_POINT('',(18.5,0.,0.));
#966=DIRECTION('',(0.,1.,0.));
#967=DIRECTION('',(0.,0.,1.));
#968=AXIS2_PLACEMENT_3D('',#965,#966,#967);
#969=CYLINDRICAL_SURFACE('',#968,2.5);
#970=ORIENTED_EDGE('',*,*,#134,.F.);
#971=EDGE_LOOP('',(#970));
#972=FACE_BOUND('',#971,.T.);
#973=ORIENTED_EDGE('',*,*,#70,.T.);
#974=EDGE_LOOP('',(#973));
#975=FACE_BOUND('',#974,.T.);
#976=ADVANCED_FACE('F195',(#972,#975),#969,.F.);
#977=CARTESIAN_POINT('',(0.,0.,-18.5));
#978=DIRECTION('',(0.,1.,0.));
#979=DIRECTION('',(0.,0.,1.));
#980=AXIS2_PLACEMENT_3D('',#977,#978,#979);
#981=CYLINDRICAL_SURFACE('',#980,2.5);
#982=ORIENTED_EDGE('',*,*,#123,.F.);
#983=EDGE_LOOP('',(#982));
#984=FACE_BOUND('',#983,.T.);
#985=ORIENTED_EDGE('',*,*,#59,.T.);
#986=EDGE_LOOP('',(#985));
#987=FACE_BOUND('',#986,.T.);
#988=ADVANCED_FACE('F89',(#984,#987),#981,.F.);
#989=CARTESIAN_POINT('',(-25.,11.5,0.));
#990=DIRECTION('',(1.,0.,0.));
#991=DIRECTION('',(0.,0.,-1.));
#992=AXIS2_PLACEMENT_3D('',#989,#990,#991);
#993=CYLINDRICAL_SURFACE('',#992,2.25);
#994=ORIENTED_EDGE('',*,*,#930,.F.);
#995=EDGE_LOOP('',(#994));
#996=FACE_BOUND('',#995,.T.);
#997=ORIENTED_EDGE('',*,*,#516,.F.);
#998=EDGE_LOOP('',(#997));
#999=FACE_BOUND('',#998,.T.);
#1000=ADVANCED_FACE('F90',(#996,#999),#993,.F.);
#1001=ORIENTED_EDGE('',*,*,#835,.F.);
#1002=EDGE_LOOP('',(#1001));
#1003=FACE_BOUND('',#1002,.T.);
#1004=ORIENTED_EDGE('',*,*,#431,.F.);
#1005=EDGE_LOOP('',(#1004));
#1006=FACE_BOUND('',#1005,.T.);
#1007=ADVANCED_FACE('F81',(#1003,#1006),#993,.F.);
#1008=CARTESIAN_POINT('',(0.,11.5,-25.));
#1009=DIRECTION('',(0.,0.,1.));
#1010=DIRECTION('',(1.,0.,0.));
#1011=AXIS2_PLACEMENT_3D('',#1008,#1009,#1010);
#1012=CYLINDRICAL_SURFACE('',#1011,2.25);
#1013=ORIENTED_EDGE('',*,*,#740,.F.);
#1014=EDGE_LOOP('',(#1013));
#1015=FACE_BOUND('',#1014,.T.);
#1016=ORIENTED_EDGE('',*,*,#261,.F.);
#1017=EDGE_LOOP('',(#1016));
#1018=FACE_BOUND('',#1017,.T.);
#1019=ADVANCED_FACE('F86',(#1015,#1018),#1012,.F.);
#1020=ORIENTED_EDGE('',*,*,#645,.F.);
#1021=EDGE_LOOP('',(#1020));
#1022=FACE_BOUND('',#1021,.T.);
#1023=ORIENTED_EDGE('',*,*,#346,.F.);
#1024=EDGE_LOOP('',(#1023));
#1025=FACE_BOUND('',#1024,.T.);
#1026=ADVANCED_FACE('F149',(#1022,#1025),#1012,.F.);
#1027=CLOSED_SHELL('',(#46,#110,#174,#534,#554,#940,#952,#964,#976,#988,#1000,#1007,#1019,#1026));
#1028=MANIFOLD_SOLID_BREP('B2',#1027);
#1029=ADVANCED_BREP_SHAPE_REPRESENTATION('',(#18,#1028),#14);
#1030=SHAPE_DEFINITION_REPRESENTATION(#9,#1029);
ENDSEC;
END-ISO-10303-21;
